VERSION 5.8 ;
BUSBITCHARS "[]" ;
DIVIDERCHAR "/" ;
UNITS
    DATABASE MICRONS 1000 ;
END UNITS

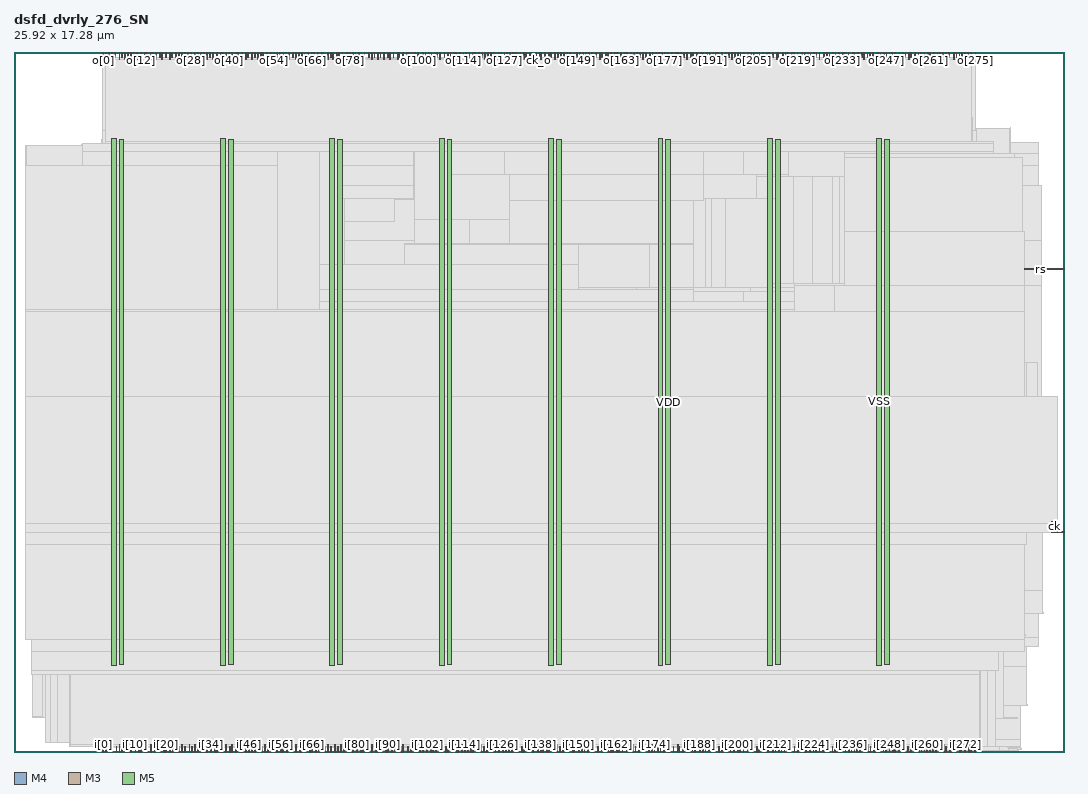
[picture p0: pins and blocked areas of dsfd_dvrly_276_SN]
MACRO dsfd_dvrly_276_SN
  FOREIGN dsfd_dvrly_276_SN 0 0 ;
  CLASS BLOCK ;
  SIZE 25.92 BY 17.28 ;
  PIN ck
    DIRECTION INPUT ;
    USE SIGNAL ;
    PORT
      LAYER M4 ;
        RECT  25.728 5.424 25.92 5.448 ;
    END
    PORT
      LAYER M4 ;
        RECT  25.621 5.424 25.74 5.688 ;
    END
  END ck
  PIN ck_o
    DIRECTION OUTPUT ;
    USE SIGNAL ;
    PORT
      LAYER M3 ;
        RECT  12.96 17.136 12.978 17.28 ;
    END
  END ck_o
  PIN i[0]
    DIRECTION INPUT ;
    USE SIGNAL ;
    PORT
      LAYER M3 ;
        RECT  2.196 0 2.214 0.144 ;
    END
  END i[0]
  PIN i[100]
    DIRECTION INPUT ;
    USE SIGNAL ;
    PORT
      LAYER M3 ;
        RECT  10.008 0 10.026 0.144 ;
    END
  END i[100]
  PIN i[101]
    DIRECTION INPUT ;
    USE SIGNAL ;
    PORT
      LAYER M5 ;
        RECT  10.08 0 10.104 0.192 ;
    END
  END i[101]
  PIN i[102]
    DIRECTION INPUT ;
    USE SIGNAL ;
    PORT
      LAYER M3 ;
        RECT  10.188 0 10.206 0.144 ;
    END
  END i[102]
  PIN i[103]
    DIRECTION INPUT ;
    USE SIGNAL ;
    PORT
      LAYER M5 ;
        RECT  10.272 0 10.296 0.192 ;
    END
  END i[103]
  PIN i[104]
    DIRECTION INPUT ;
    USE SIGNAL ;
    PORT
      LAYER M3 ;
        RECT  10.332 0 10.35 0.144 ;
    END
  END i[104]
  PIN i[105]
    DIRECTION INPUT ;
    USE SIGNAL ;
    PORT
      LAYER M5 ;
        RECT  10.416 0 10.44 0.192 ;
    END
  END i[105]
  PIN i[106]
    DIRECTION INPUT ;
    USE SIGNAL ;
    PORT
      LAYER M3 ;
        RECT  10.476 0 10.494 0.144 ;
    END
  END i[106]
  PIN i[107]
    DIRECTION INPUT ;
    USE SIGNAL ;
    PORT
      LAYER M5 ;
        RECT  10.56 0 10.584 0.192 ;
    END
  END i[107]
  PIN i[108]
    DIRECTION INPUT ;
    USE SIGNAL ;
    PORT
      LAYER M3 ;
        RECT  10.656 0 10.674 0.144 ;
    END
  END i[108]
  PIN i[109]
    DIRECTION INPUT ;
    USE SIGNAL ;
    PORT
      LAYER M5 ;
        RECT  10.704 0 10.728 0.192 ;
    END
  END i[109]
  PIN i[10]
    DIRECTION INPUT ;
    USE SIGNAL ;
    PORT
      LAYER M3 ;
        RECT  2.988 0 3.006 0.144 ;
    END
  END i[10]
  PIN i[110]
    DIRECTION INPUT ;
    USE SIGNAL ;
    PORT
      LAYER M3 ;
        RECT  10.8 0 10.818 0.144 ;
    END
  END i[110]
  PIN i[111]
    DIRECTION INPUT ;
    USE SIGNAL ;
    PORT
      LAYER M5 ;
        RECT  10.896 0 10.92 0.192 ;
    END
  END i[111]
  PIN i[112]
    DIRECTION INPUT ;
    USE SIGNAL ;
    PORT
      LAYER M3 ;
        RECT  10.944 0 10.962 0.144 ;
    END
  END i[112]
  PIN i[113]
    DIRECTION INPUT ;
    USE SIGNAL ;
    PORT
      LAYER M5 ;
        RECT  11.04 0 11.064 0.192 ;
    END
  END i[113]
  PIN i[114]
    DIRECTION INPUT ;
    USE SIGNAL ;
    PORT
      LAYER M3 ;
        RECT  11.124 0 11.142 0.144 ;
    END
  END i[114]
  PIN i[115]
    DIRECTION INPUT ;
    USE SIGNAL ;
    PORT
      LAYER M5 ;
        RECT  11.184 0 11.208 0.192 ;
    END
  END i[115]
  PIN i[116]
    DIRECTION INPUT ;
    USE SIGNAL ;
    PORT
      LAYER M3 ;
        RECT  11.268 0 11.286 0.144 ;
    END
  END i[116]
  PIN i[117]
    DIRECTION INPUT ;
    USE SIGNAL ;
    PORT
      LAYER M5 ;
        RECT  11.328 0 11.352 0.192 ;
    END
  END i[117]
  PIN i[118]
    DIRECTION INPUT ;
    USE SIGNAL ;
    PORT
      LAYER M3 ;
        RECT  11.412 0 11.43 0.144 ;
    END
  END i[118]
  PIN i[119]
    DIRECTION INPUT ;
    USE SIGNAL ;
    PORT
      LAYER M5 ;
        RECT  11.52 0 11.544 0.192 ;
    END
  END i[119]
  PIN i[11]
    DIRECTION INPUT ;
    USE SIGNAL ;
    PORT
      LAYER M5 ;
        RECT  3.072 0 3.096 0.192 ;
    END
  END i[11]
  PIN i[120]
    DIRECTION INPUT ;
    USE SIGNAL ;
    PORT
      LAYER M3 ;
        RECT  11.592 0 11.61 0.144 ;
    END
  END i[120]
  PIN i[121]
    DIRECTION INPUT ;
    USE SIGNAL ;
    PORT
      LAYER M5 ;
        RECT  11.664 0 11.688 0.192 ;
    END
  END i[121]
  PIN i[122]
    DIRECTION INPUT ;
    USE SIGNAL ;
    PORT
      LAYER M3 ;
        RECT  11.736 0 11.754 0.144 ;
    END
  END i[122]
  PIN i[123]
    DIRECTION INPUT ;
    USE SIGNAL ;
    PORT
      LAYER M5 ;
        RECT  11.808 0 11.832 0.192 ;
    END
  END i[123]
  PIN i[124]
    DIRECTION INPUT ;
    USE SIGNAL ;
    PORT
      LAYER M3 ;
        RECT  11.88 0 11.898 0.144 ;
    END
  END i[124]
  PIN i[125]
    DIRECTION INPUT ;
    USE SIGNAL ;
    PORT
      LAYER M5 ;
        RECT  11.952 0 11.976 0.192 ;
    END
  END i[125]
  PIN i[126]
    DIRECTION INPUT ;
    USE SIGNAL ;
    PORT
      LAYER M3 ;
        RECT  12.06 0 12.078 0.144 ;
    END
  END i[126]
  PIN i[127]
    DIRECTION INPUT ;
    USE SIGNAL ;
    PORT
      LAYER M5 ;
        RECT  12.144 0 12.168 0.192 ;
    END
  END i[127]
  PIN i[128]
    DIRECTION INPUT ;
    USE SIGNAL ;
    PORT
      LAYER M3 ;
        RECT  12.204 0 12.222 0.144 ;
    END
  END i[128]
  PIN i[129]
    DIRECTION INPUT ;
    USE SIGNAL ;
    PORT
      LAYER M5 ;
        RECT  12.288 0 12.312 0.192 ;
    END
  END i[129]
  PIN i[12]
    DIRECTION INPUT ;
    USE SIGNAL ;
    PORT
      LAYER M3 ;
        RECT  3.132 0 3.15 0.144 ;
    END
  END i[12]
  PIN i[130]
    DIRECTION INPUT ;
    USE SIGNAL ;
    PORT
      LAYER M3 ;
        RECT  12.348 0 12.366 0.144 ;
    END
  END i[130]
  PIN i[131]
    DIRECTION INPUT ;
    USE SIGNAL ;
    PORT
      LAYER M5 ;
        RECT  12.432 0 12.456 0.192 ;
    END
  END i[131]
  PIN i[132]
    DIRECTION INPUT ;
    USE SIGNAL ;
    PORT
      LAYER M3 ;
        RECT  12.528 0 12.546 0.144 ;
    END
  END i[132]
  PIN i[133]
    DIRECTION INPUT ;
    USE SIGNAL ;
    PORT
      LAYER M5 ;
        RECT  12.576 0 12.6 0.192 ;
    END
  END i[133]
  PIN i[134]
    DIRECTION INPUT ;
    USE SIGNAL ;
    PORT
      LAYER M3 ;
        RECT  12.672 0 12.69 0.144 ;
    END
  END i[134]
  PIN i[135]
    DIRECTION INPUT ;
    USE SIGNAL ;
    PORT
      LAYER M5 ;
        RECT  12.768 0 12.792 0.192 ;
    END
  END i[135]
  PIN i[136]
    DIRECTION INPUT ;
    USE SIGNAL ;
    PORT
      LAYER M3 ;
        RECT  12.816 0 12.834 0.144 ;
    END
  END i[136]
  PIN i[137]
    DIRECTION INPUT ;
    USE SIGNAL ;
    PORT
      LAYER M5 ;
        RECT  12.912 0 12.936 0.192 ;
    END
  END i[137]
  PIN i[138]
    DIRECTION INPUT ;
    USE SIGNAL ;
    PORT
      LAYER M3 ;
        RECT  12.996 0 13.014 0.144 ;
    END
  END i[138]
  PIN i[139]
    DIRECTION INPUT ;
    USE SIGNAL ;
    PORT
      LAYER M5 ;
        RECT  13.056 0 13.08 0.192 ;
    END
  END i[139]
  PIN i[13]
    DIRECTION INPUT ;
    USE SIGNAL ;
    PORT
      LAYER M5 ;
        RECT  3.216 0 3.24 0.192 ;
    END
  END i[13]
  PIN i[140]
    DIRECTION INPUT ;
    USE SIGNAL ;
    PORT
      LAYER M3 ;
        RECT  13.14 0 13.158 0.144 ;
    END
  END i[140]
  PIN i[141]
    DIRECTION INPUT ;
    USE SIGNAL ;
    PORT
      LAYER M5 ;
        RECT  13.2 0 13.224 0.192 ;
    END
  END i[141]
  PIN i[142]
    DIRECTION INPUT ;
    USE SIGNAL ;
    PORT
      LAYER M3 ;
        RECT  13.32 0 13.338 0.144 ;
    END
  END i[142]
  PIN i[143]
    DIRECTION INPUT ;
    USE SIGNAL ;
    PORT
      LAYER M5 ;
        RECT  13.392 0 13.416 0.192 ;
    END
  END i[143]
  PIN i[144]
    DIRECTION INPUT ;
    USE SIGNAL ;
    PORT
      LAYER M3 ;
        RECT  13.464 0 13.482 0.144 ;
    END
  END i[144]
  PIN i[145]
    DIRECTION INPUT ;
    USE SIGNAL ;
    PORT
      LAYER M5 ;
        RECT  13.536 0 13.56 0.192 ;
    END
  END i[145]
  PIN i[146]
    DIRECTION INPUT ;
    USE SIGNAL ;
    PORT
      LAYER M3 ;
        RECT  13.608 0 13.626 0.144 ;
    END
  END i[146]
  PIN i[147]
    DIRECTION INPUT ;
    USE SIGNAL ;
    PORT
      LAYER M5 ;
        RECT  13.68 0 13.704 0.192 ;
    END
  END i[147]
  PIN i[148]
    DIRECTION INPUT ;
    USE SIGNAL ;
    PORT
      LAYER M3 ;
        RECT  13.788 0 13.806 0.144 ;
    END
  END i[148]
  PIN i[149]
    DIRECTION INPUT ;
    USE SIGNAL ;
    PORT
      LAYER M5 ;
        RECT  13.824 0 13.848 0.192 ;
    END
  END i[149]
  PIN i[14]
    DIRECTION INPUT ;
    USE SIGNAL ;
    PORT
      LAYER M3 ;
        RECT  3.276 0 3.294 0.144 ;
    END
  END i[14]
  PIN i[150]
    DIRECTION INPUT ;
    USE SIGNAL ;
    PORT
      LAYER M3 ;
        RECT  13.932 0 13.95 0.144 ;
    END
  END i[150]
  PIN i[151]
    DIRECTION INPUT ;
    USE SIGNAL ;
    PORT
      LAYER M5 ;
        RECT  14.016 0 14.04 0.192 ;
    END
  END i[151]
  PIN i[152]
    DIRECTION INPUT ;
    USE SIGNAL ;
    PORT
      LAYER M3 ;
        RECT  14.076 0 14.094 0.144 ;
    END
  END i[152]
  PIN i[153]
    DIRECTION INPUT ;
    USE SIGNAL ;
    PORT
      LAYER M5 ;
        RECT  14.16 0 14.184 0.192 ;
    END
  END i[153]
  PIN i[154]
    DIRECTION INPUT ;
    USE SIGNAL ;
    PORT
      LAYER M3 ;
        RECT  14.256 0 14.274 0.144 ;
    END
  END i[154]
  PIN i[155]
    DIRECTION INPUT ;
    USE SIGNAL ;
    PORT
      LAYER M5 ;
        RECT  14.304 0 14.328 0.192 ;
    END
  END i[155]
  PIN i[156]
    DIRECTION INPUT ;
    USE SIGNAL ;
    PORT
      LAYER M3 ;
        RECT  14.4 0 14.418 0.144 ;
    END
  END i[156]
  PIN i[157]
    DIRECTION INPUT ;
    USE SIGNAL ;
    PORT
      LAYER M5 ;
        RECT  14.496 0 14.52 0.192 ;
    END
  END i[157]
  PIN i[158]
    DIRECTION INPUT ;
    USE SIGNAL ;
    PORT
      LAYER M3 ;
        RECT  14.544 0 14.562 0.144 ;
    END
  END i[158]
  PIN i[159]
    DIRECTION INPUT ;
    USE SIGNAL ;
    PORT
      LAYER M5 ;
        RECT  14.64 0 14.664 0.192 ;
    END
  END i[159]
  PIN i[15]
    DIRECTION INPUT ;
    USE SIGNAL ;
    PORT
      LAYER M5 ;
        RECT  3.36 0 3.384 0.192 ;
    END
  END i[15]
  PIN i[160]
    DIRECTION INPUT ;
    USE SIGNAL ;
    PORT
      LAYER M3 ;
        RECT  14.724 0 14.742 0.144 ;
    END
  END i[160]
  PIN i[161]
    DIRECTION INPUT ;
    USE SIGNAL ;
    PORT
      LAYER M5 ;
        RECT  14.784 0 14.808 0.192 ;
    END
  END i[161]
  PIN i[162]
    DIRECTION INPUT ;
    USE SIGNAL ;
    PORT
      LAYER M3 ;
        RECT  14.868 0 14.886 0.144 ;
    END
  END i[162]
  PIN i[163]
    DIRECTION INPUT ;
    USE SIGNAL ;
    PORT
      LAYER M5 ;
        RECT  14.928 0 14.952 0.192 ;
    END
  END i[163]
  PIN i[164]
    DIRECTION INPUT ;
    USE SIGNAL ;
    PORT
      LAYER M3 ;
        RECT  15.012 0 15.03 0.144 ;
    END
  END i[164]
  PIN i[165]
    DIRECTION INPUT ;
    USE SIGNAL ;
    PORT
      LAYER M5 ;
        RECT  15.12 0 15.144 0.192 ;
    END
  END i[165]
  PIN i[166]
    DIRECTION INPUT ;
    USE SIGNAL ;
    PORT
      LAYER M3 ;
        RECT  15.192 0 15.21 0.144 ;
    END
  END i[166]
  PIN i[167]
    DIRECTION INPUT ;
    USE SIGNAL ;
    PORT
      LAYER M5 ;
        RECT  15.264 0 15.288 0.192 ;
    END
  END i[167]
  PIN i[168]
    DIRECTION INPUT ;
    USE SIGNAL ;
    PORT
      LAYER M3 ;
        RECT  15.336 0 15.354 0.144 ;
    END
  END i[168]
  PIN i[169]
    DIRECTION INPUT ;
    USE SIGNAL ;
    PORT
      LAYER M5 ;
        RECT  15.408 0 15.432 0.192 ;
    END
  END i[169]
  PIN i[16]
    DIRECTION INPUT ;
    USE SIGNAL ;
    PORT
      LAYER M3 ;
        RECT  3.456 0 3.474 0.144 ;
    END
  END i[16]
  PIN i[170]
    DIRECTION INPUT ;
    USE SIGNAL ;
    PORT
      LAYER M3 ;
        RECT  15.48 0 15.498 0.144 ;
    END
  END i[170]
  PIN i[171]
    DIRECTION INPUT ;
    USE SIGNAL ;
    PORT
      LAYER M5 ;
        RECT  15.552 0 15.576 0.192 ;
    END
  END i[171]
  PIN i[172]
    DIRECTION INPUT ;
    USE SIGNAL ;
    PORT
      LAYER M3 ;
        RECT  15.66 0 15.678 0.144 ;
    END
  END i[172]
  PIN i[173]
    DIRECTION INPUT ;
    USE SIGNAL ;
    PORT
      LAYER M5 ;
        RECT  15.744 0 15.768 0.192 ;
    END
  END i[173]
  PIN i[174]
    DIRECTION INPUT ;
    USE SIGNAL ;
    PORT
      LAYER M3 ;
        RECT  15.804 0 15.822 0.144 ;
    END
  END i[174]
  PIN i[175]
    DIRECTION INPUT ;
    USE SIGNAL ;
    PORT
      LAYER M5 ;
        RECT  15.888 0 15.912 0.192 ;
    END
  END i[175]
  PIN i[176]
    DIRECTION INPUT ;
    USE SIGNAL ;
    PORT
      LAYER M3 ;
        RECT  15.948 0 15.966 0.144 ;
    END
  END i[176]
  PIN i[177]
    DIRECTION INPUT ;
    USE SIGNAL ;
    PORT
      LAYER M5 ;
        RECT  16.032 0 16.056 0.192 ;
    END
  END i[177]
  PIN i[178]
    DIRECTION INPUT ;
    USE SIGNAL ;
    PORT
      LAYER M3 ;
        RECT  16.128 0 16.146 0.144 ;
    END
  END i[178]
  PIN i[179]
    DIRECTION INPUT ;
    USE SIGNAL ;
    PORT
      LAYER M5 ;
        RECT  16.176 0 16.2 0.192 ;
    END
  END i[179]
  PIN i[17]
    DIRECTION INPUT ;
    USE SIGNAL ;
    PORT
      LAYER M5 ;
        RECT  3.504 0 3.528 0.192 ;
    END
  END i[17]
  PIN i[180]
    DIRECTION INPUT ;
    USE SIGNAL ;
    PORT
      LAYER M3 ;
        RECT  16.272 0 16.29 0.144 ;
    END
  END i[180]
  PIN i[181]
    DIRECTION INPUT ;
    USE SIGNAL ;
    PORT
      LAYER M5 ;
        RECT  16.368 0 16.392 0.192 ;
    END
  END i[181]
  PIN i[182]
    DIRECTION INPUT ;
    USE SIGNAL ;
    PORT
      LAYER M3 ;
        RECT  16.416 0 16.434 0.144 ;
    END
  END i[182]
  PIN i[183]
    DIRECTION INPUT ;
    USE SIGNAL ;
    PORT
      LAYER M5 ;
        RECT  16.512 0 16.536 0.192 ;
    END
  END i[183]
  PIN i[184]
    DIRECTION INPUT ;
    USE SIGNAL ;
    PORT
      LAYER M3 ;
        RECT  16.596 0 16.614 0.144 ;
    END
  END i[184]
  PIN i[185]
    DIRECTION INPUT ;
    USE SIGNAL ;
    PORT
      LAYER M5 ;
        RECT  16.656 0 16.68 0.192 ;
    END
  END i[185]
  PIN i[186]
    DIRECTION INPUT ;
    USE SIGNAL ;
    PORT
      LAYER M3 ;
        RECT  16.74 0 16.758 0.144 ;
    END
  END i[186]
  PIN i[187]
    DIRECTION INPUT ;
    USE SIGNAL ;
    PORT
      LAYER M5 ;
        RECT  16.8 0 16.824 0.192 ;
    END
  END i[187]
  PIN i[188]
    DIRECTION INPUT ;
    USE SIGNAL ;
    PORT
      LAYER M3 ;
        RECT  16.92 0 16.938 0.144 ;
    END
  END i[188]
  PIN i[189]
    DIRECTION INPUT ;
    USE SIGNAL ;
    PORT
      LAYER M5 ;
        RECT  16.992 0 17.016 0.192 ;
    END
  END i[189]
  PIN i[18]
    DIRECTION INPUT ;
    USE SIGNAL ;
    PORT
      LAYER M3 ;
        RECT  3.6 0 3.618 0.144 ;
    END
  END i[18]
  PIN i[190]
    DIRECTION INPUT ;
    USE SIGNAL ;
    PORT
      LAYER M3 ;
        RECT  17.064 0 17.082 0.144 ;
    END
  END i[190]
  PIN i[191]
    DIRECTION INPUT ;
    USE SIGNAL ;
    PORT
      LAYER M5 ;
        RECT  17.136 0 17.16 0.192 ;
    END
  END i[191]
  PIN i[192]
    DIRECTION INPUT ;
    USE SIGNAL ;
    PORT
      LAYER M3 ;
        RECT  17.208 0 17.226 0.144 ;
    END
  END i[192]
  PIN i[193]
    DIRECTION INPUT ;
    USE SIGNAL ;
    PORT
      LAYER M5 ;
        RECT  17.28 0 17.304 0.192 ;
    END
  END i[193]
  PIN i[194]
    DIRECTION INPUT ;
    USE SIGNAL ;
    PORT
      LAYER M3 ;
        RECT  17.388 0 17.406 0.144 ;
    END
  END i[194]
  PIN i[195]
    DIRECTION INPUT ;
    USE SIGNAL ;
    PORT
      LAYER M5 ;
        RECT  17.472 0 17.496 0.192 ;
    END
  END i[195]
  PIN i[196]
    DIRECTION INPUT ;
    USE SIGNAL ;
    PORT
      LAYER M3 ;
        RECT  17.532 0 17.55 0.144 ;
    END
  END i[196]
  PIN i[197]
    DIRECTION INPUT ;
    USE SIGNAL ;
    PORT
      LAYER M5 ;
        RECT  17.616 0 17.64 0.192 ;
    END
  END i[197]
  PIN i[198]
    DIRECTION INPUT ;
    USE SIGNAL ;
    PORT
      LAYER M3 ;
        RECT  17.676 0 17.694 0.144 ;
    END
  END i[198]
  PIN i[199]
    DIRECTION INPUT ;
    USE SIGNAL ;
    PORT
      LAYER M5 ;
        RECT  17.76 0 17.784 0.192 ;
    END
  END i[199]
  PIN i[19]
    DIRECTION INPUT ;
    USE SIGNAL ;
    PORT
      LAYER M5 ;
        RECT  3.696 0 3.72 0.192 ;
    END
  END i[19]
  PIN i[1]
    DIRECTION INPUT ;
    USE SIGNAL ;
    PORT
      LAYER M5 ;
        RECT  2.256 0 2.28 0.192 ;
    END
  END i[1]
  PIN i[200]
    DIRECTION INPUT ;
    USE SIGNAL ;
    PORT
      LAYER M3 ;
        RECT  17.856 0 17.874 0.144 ;
    END
  END i[200]
  PIN i[201]
    DIRECTION INPUT ;
    USE SIGNAL ;
    PORT
      LAYER M5 ;
        RECT  17.904 0 17.928 0.192 ;
    END
  END i[201]
  PIN i[202]
    DIRECTION INPUT ;
    USE SIGNAL ;
    PORT
      LAYER M3 ;
        RECT  18 0 18.018 0.144 ;
    END
  END i[202]
  PIN i[203]
    DIRECTION INPUT ;
    USE SIGNAL ;
    PORT
      LAYER M5 ;
        RECT  18.096 0 18.12 0.192 ;
    END
  END i[203]
  PIN i[204]
    DIRECTION INPUT ;
    USE SIGNAL ;
    PORT
      LAYER M3 ;
        RECT  18.144 0 18.162 0.144 ;
    END
  END i[204]
  PIN i[205]
    DIRECTION INPUT ;
    USE SIGNAL ;
    PORT
      LAYER M5 ;
        RECT  18.24 0 18.264 0.192 ;
    END
  END i[205]
  PIN i[206]
    DIRECTION INPUT ;
    USE SIGNAL ;
    PORT
      LAYER M3 ;
        RECT  18.324 0 18.342 0.144 ;
    END
  END i[206]
  PIN i[207]
    DIRECTION INPUT ;
    USE SIGNAL ;
    PORT
      LAYER M5 ;
        RECT  18.384 0 18.408 0.192 ;
    END
  END i[207]
  PIN i[208]
    DIRECTION INPUT ;
    USE SIGNAL ;
    PORT
      LAYER M3 ;
        RECT  18.468 0 18.486 0.144 ;
    END
  END i[208]
  PIN i[209]
    DIRECTION INPUT ;
    USE SIGNAL ;
    PORT
      LAYER M5 ;
        RECT  18.528 0 18.552 0.192 ;
    END
  END i[209]
  PIN i[20]
    DIRECTION INPUT ;
    USE SIGNAL ;
    PORT
      LAYER M3 ;
        RECT  3.744 0 3.762 0.144 ;
    END
  END i[20]
  PIN i[210]
    DIRECTION INPUT ;
    USE SIGNAL ;
    PORT
      LAYER M3 ;
        RECT  18.612 0 18.63 0.144 ;
    END
  END i[210]
  PIN i[211]
    DIRECTION INPUT ;
    USE SIGNAL ;
    PORT
      LAYER M5 ;
        RECT  18.72 0 18.744 0.192 ;
    END
  END i[211]
  PIN i[212]
    DIRECTION INPUT ;
    USE SIGNAL ;
    PORT
      LAYER M3 ;
        RECT  18.792 0 18.81 0.144 ;
    END
  END i[212]
  PIN i[213]
    DIRECTION INPUT ;
    USE SIGNAL ;
    PORT
      LAYER M5 ;
        RECT  18.864 0 18.888 0.192 ;
    END
  END i[213]
  PIN i[214]
    DIRECTION INPUT ;
    USE SIGNAL ;
    PORT
      LAYER M3 ;
        RECT  18.936 0 18.954 0.144 ;
    END
  END i[214]
  PIN i[215]
    DIRECTION INPUT ;
    USE SIGNAL ;
    PORT
      LAYER M5 ;
        RECT  19.008 0 19.032 0.192 ;
    END
  END i[215]
  PIN i[216]
    DIRECTION INPUT ;
    USE SIGNAL ;
    PORT
      LAYER M3 ;
        RECT  19.08 0 19.098 0.144 ;
    END
  END i[216]
  PIN i[217]
    DIRECTION INPUT ;
    USE SIGNAL ;
    PORT
      LAYER M5 ;
        RECT  19.152 0 19.176 0.192 ;
    END
  END i[217]
  PIN i[218]
    DIRECTION INPUT ;
    USE SIGNAL ;
    PORT
      LAYER M3 ;
        RECT  19.26 0 19.278 0.144 ;
    END
  END i[218]
  PIN i[219]
    DIRECTION INPUT ;
    USE SIGNAL ;
    PORT
      LAYER M5 ;
        RECT  19.344 0 19.368 0.192 ;
    END
  END i[219]
  PIN i[21]
    DIRECTION INPUT ;
    USE SIGNAL ;
    PORT
      LAYER M5 ;
        RECT  3.84 0 3.864 0.192 ;
    END
  END i[21]
  PIN i[220]
    DIRECTION INPUT ;
    USE SIGNAL ;
    PORT
      LAYER M3 ;
        RECT  19.404 0 19.422 0.144 ;
    END
  END i[220]
  PIN i[221]
    DIRECTION INPUT ;
    USE SIGNAL ;
    PORT
      LAYER M5 ;
        RECT  19.488 0 19.512 0.192 ;
    END
  END i[221]
  PIN i[222]
    DIRECTION INPUT ;
    USE SIGNAL ;
    PORT
      LAYER M3 ;
        RECT  19.548 0 19.566 0.144 ;
    END
  END i[222]
  PIN i[223]
    DIRECTION INPUT ;
    USE SIGNAL ;
    PORT
      LAYER M5 ;
        RECT  19.632 0 19.656 0.192 ;
    END
  END i[223]
  PIN i[224]
    DIRECTION INPUT ;
    USE SIGNAL ;
    PORT
      LAYER M3 ;
        RECT  19.728 0 19.746 0.144 ;
    END
  END i[224]
  PIN i[225]
    DIRECTION INPUT ;
    USE SIGNAL ;
    PORT
      LAYER M5 ;
        RECT  19.776 0 19.8 0.192 ;
    END
  END i[225]
  PIN i[226]
    DIRECTION INPUT ;
    USE SIGNAL ;
    PORT
      LAYER M3 ;
        RECT  19.872 0 19.89 0.144 ;
    END
  END i[226]
  PIN i[227]
    DIRECTION INPUT ;
    USE SIGNAL ;
    PORT
      LAYER M5 ;
        RECT  19.968 0 19.992 0.192 ;
    END
  END i[227]
  PIN i[228]
    DIRECTION INPUT ;
    USE SIGNAL ;
    PORT
      LAYER M3 ;
        RECT  20.016 0 20.034 0.144 ;
    END
  END i[228]
  PIN i[229]
    DIRECTION INPUT ;
    USE SIGNAL ;
    PORT
      LAYER M5 ;
        RECT  20.112 0 20.136 0.192 ;
    END
  END i[229]
  PIN i[22]
    DIRECTION INPUT ;
    USE SIGNAL ;
    PORT
      LAYER M3 ;
        RECT  3.924 0 3.942 0.144 ;
    END
  END i[22]
  PIN i[230]
    DIRECTION INPUT ;
    USE SIGNAL ;
    PORT
      LAYER M3 ;
        RECT  20.196 0 20.214 0.144 ;
    END
  END i[230]
  PIN i[231]
    DIRECTION INPUT ;
    USE SIGNAL ;
    PORT
      LAYER M5 ;
        RECT  20.256 0 20.28 0.192 ;
    END
  END i[231]
  PIN i[232]
    DIRECTION INPUT ;
    USE SIGNAL ;
    PORT
      LAYER M3 ;
        RECT  20.34 0 20.358 0.144 ;
    END
  END i[232]
  PIN i[233]
    DIRECTION INPUT ;
    USE SIGNAL ;
    PORT
      LAYER M5 ;
        RECT  20.4 0 20.424 0.192 ;
    END
  END i[233]
  PIN i[234]
    DIRECTION INPUT ;
    USE SIGNAL ;
    PORT
      LAYER M3 ;
        RECT  20.52 0 20.538 0.144 ;
    END
  END i[234]
  PIN i[235]
    DIRECTION INPUT ;
    USE SIGNAL ;
    PORT
      LAYER M5 ;
        RECT  20.592 0 20.616 0.192 ;
    END
  END i[235]
  PIN i[236]
    DIRECTION INPUT ;
    USE SIGNAL ;
    PORT
      LAYER M3 ;
        RECT  20.664 0 20.682 0.144 ;
    END
  END i[236]
  PIN i[237]
    DIRECTION INPUT ;
    USE SIGNAL ;
    PORT
      LAYER M5 ;
        RECT  20.736 0 20.76 0.192 ;
    END
  END i[237]
  PIN i[238]
    DIRECTION INPUT ;
    USE SIGNAL ;
    PORT
      LAYER M3 ;
        RECT  20.808 0 20.826 0.144 ;
    END
  END i[238]
  PIN i[239]
    DIRECTION INPUT ;
    USE SIGNAL ;
    PORT
      LAYER M5 ;
        RECT  20.88 0 20.904 0.192 ;
    END
  END i[239]
  PIN i[23]
    DIRECTION INPUT ;
    USE SIGNAL ;
    PORT
      LAYER M5 ;
        RECT  3.984 0 4.008 0.192 ;
    END
  END i[23]
  PIN i[240]
    DIRECTION INPUT ;
    USE SIGNAL ;
    PORT
      LAYER M3 ;
        RECT  20.988 0 21.006 0.144 ;
    END
  END i[240]
  PIN i[241]
    DIRECTION INPUT ;
    USE SIGNAL ;
    PORT
      LAYER M5 ;
        RECT  21.072 0 21.096 0.192 ;
    END
  END i[241]
  PIN i[242]
    DIRECTION INPUT ;
    USE SIGNAL ;
    PORT
      LAYER M3 ;
        RECT  21.132 0 21.15 0.144 ;
    END
  END i[242]
  PIN i[243]
    DIRECTION INPUT ;
    USE SIGNAL ;
    PORT
      LAYER M5 ;
        RECT  21.216 0 21.24 0.192 ;
    END
  END i[243]
  PIN i[244]
    DIRECTION INPUT ;
    USE SIGNAL ;
    PORT
      LAYER M3 ;
        RECT  21.276 0 21.294 0.144 ;
    END
  END i[244]
  PIN i[245]
    DIRECTION INPUT ;
    USE SIGNAL ;
    PORT
      LAYER M5 ;
        RECT  21.36 0 21.384 0.192 ;
    END
  END i[245]
  PIN i[246]
    DIRECTION INPUT ;
    USE SIGNAL ;
    PORT
      LAYER M3 ;
        RECT  21.456 0 21.474 0.144 ;
    END
  END i[246]
  PIN i[247]
    DIRECTION INPUT ;
    USE SIGNAL ;
    PORT
      LAYER M5 ;
        RECT  21.504 0 21.528 0.192 ;
    END
  END i[247]
  PIN i[248]
    DIRECTION INPUT ;
    USE SIGNAL ;
    PORT
      LAYER M3 ;
        RECT  21.6 0 21.618 0.144 ;
    END
  END i[248]
  PIN i[249]
    DIRECTION INPUT ;
    USE SIGNAL ;
    PORT
      LAYER M5 ;
        RECT  21.696 0 21.72 0.192 ;
    END
  END i[249]
  PIN i[24]
    DIRECTION INPUT ;
    USE SIGNAL ;
    PORT
      LAYER M3 ;
        RECT  4.068 0 4.086 0.144 ;
    END
  END i[24]
  PIN i[250]
    DIRECTION INPUT ;
    USE SIGNAL ;
    PORT
      LAYER M3 ;
        RECT  21.744 0 21.762 0.144 ;
    END
  END i[250]
  PIN i[251]
    DIRECTION INPUT ;
    USE SIGNAL ;
    PORT
      LAYER M5 ;
        RECT  21.84 0 21.864 0.192 ;
    END
  END i[251]
  PIN i[252]
    DIRECTION INPUT ;
    USE SIGNAL ;
    PORT
      LAYER M3 ;
        RECT  21.924 0 21.942 0.144 ;
    END
  END i[252]
  PIN i[253]
    DIRECTION INPUT ;
    USE SIGNAL ;
    PORT
      LAYER M5 ;
        RECT  21.984 0 22.008 0.192 ;
    END
  END i[253]
  PIN i[254]
    DIRECTION INPUT ;
    USE SIGNAL ;
    PORT
      LAYER M3 ;
        RECT  22.068 0 22.086 0.144 ;
    END
  END i[254]
  PIN i[255]
    DIRECTION INPUT ;
    USE SIGNAL ;
    PORT
      LAYER M5 ;
        RECT  22.128 0 22.152 0.192 ;
    END
  END i[255]
  PIN i[256]
    DIRECTION INPUT ;
    USE SIGNAL ;
    PORT
      LAYER M3 ;
        RECT  22.212 0 22.23 0.144 ;
    END
  END i[256]
  PIN i[257]
    DIRECTION INPUT ;
    USE SIGNAL ;
    PORT
      LAYER M5 ;
        RECT  22.32 0 22.344 0.192 ;
    END
  END i[257]
  PIN i[258]
    DIRECTION INPUT ;
    USE SIGNAL ;
    PORT
      LAYER M3 ;
        RECT  22.392 0 22.41 0.144 ;
    END
  END i[258]
  PIN i[259]
    DIRECTION INPUT ;
    USE SIGNAL ;
    PORT
      LAYER M5 ;
        RECT  22.464 0 22.488 0.192 ;
    END
  END i[259]
  PIN i[25]
    DIRECTION INPUT ;
    USE SIGNAL ;
    PORT
      LAYER M5 ;
        RECT  4.128 0 4.152 0.192 ;
    END
  END i[25]
  PIN i[260]
    DIRECTION INPUT ;
    USE SIGNAL ;
    PORT
      LAYER M3 ;
        RECT  22.536 0 22.554 0.144 ;
    END
  END i[260]
  PIN i[261]
    DIRECTION INPUT ;
    USE SIGNAL ;
    PORT
      LAYER M5 ;
        RECT  22.608 0 22.632 0.192 ;
    END
  END i[261]
  PIN i[262]
    DIRECTION INPUT ;
    USE SIGNAL ;
    PORT
      LAYER M3 ;
        RECT  22.68 0 22.698 0.144 ;
    END
  END i[262]
  PIN i[263]
    DIRECTION INPUT ;
    USE SIGNAL ;
    PORT
      LAYER M5 ;
        RECT  22.752 0 22.776 0.192 ;
    END
  END i[263]
  PIN i[264]
    DIRECTION INPUT ;
    USE SIGNAL ;
    PORT
      LAYER M3 ;
        RECT  22.86 0 22.878 0.144 ;
    END
  END i[264]
  PIN i[265]
    DIRECTION INPUT ;
    USE SIGNAL ;
    PORT
      LAYER M5 ;
        RECT  22.944 0 22.968 0.192 ;
    END
  END i[265]
  PIN i[266]
    DIRECTION INPUT ;
    USE SIGNAL ;
    PORT
      LAYER M3 ;
        RECT  23.004 0 23.022 0.144 ;
    END
  END i[266]
  PIN i[267]
    DIRECTION INPUT ;
    USE SIGNAL ;
    PORT
      LAYER M5 ;
        RECT  23.088 0 23.112 0.192 ;
    END
  END i[267]
  PIN i[268]
    DIRECTION INPUT ;
    USE SIGNAL ;
    PORT
      LAYER M3 ;
        RECT  23.148 0 23.166 0.144 ;
    END
  END i[268]
  PIN i[269]
    DIRECTION INPUT ;
    USE SIGNAL ;
    PORT
      LAYER M5 ;
        RECT  23.232 0 23.256 0.192 ;
    END
  END i[269]
  PIN i[26]
    DIRECTION INPUT ;
    USE SIGNAL ;
    PORT
      LAYER M3 ;
        RECT  4.212 0 4.23 0.144 ;
    END
  END i[26]
  PIN i[270]
    DIRECTION INPUT ;
    USE SIGNAL ;
    PORT
      LAYER M3 ;
        RECT  23.328 0 23.346 0.144 ;
    END
  END i[270]
  PIN i[271]
    DIRECTION INPUT ;
    USE SIGNAL ;
    PORT
      LAYER M5 ;
        RECT  23.376 0 23.4 0.192 ;
    END
  END i[271]
  PIN i[272]
    DIRECTION INPUT ;
    USE SIGNAL ;
    PORT
      LAYER M3 ;
        RECT  23.472 0 23.49 0.144 ;
    END
  END i[272]
  PIN i[273]
    DIRECTION INPUT ;
    USE SIGNAL ;
    PORT
      LAYER M5 ;
        RECT  23.568 0 23.592 0.192 ;
    END
  END i[273]
  PIN i[274]
    DIRECTION INPUT ;
    USE SIGNAL ;
    PORT
      LAYER M3 ;
        RECT  23.616 0 23.634 0.144 ;
    END
  END i[274]
  PIN i[275]
    DIRECTION INPUT ;
    USE SIGNAL ;
    PORT
      LAYER M5 ;
        RECT  23.712 0 23.736 0.192 ;
    END
  END i[275]
  PIN i[27]
    DIRECTION INPUT ;
    USE SIGNAL ;
    PORT
      LAYER M5 ;
        RECT  4.32 0 4.344 0.192 ;
    END
  END i[27]
  PIN i[28]
    DIRECTION INPUT ;
    USE SIGNAL ;
    PORT
      LAYER M3 ;
        RECT  4.392 0 4.41 0.144 ;
    END
  END i[28]
  PIN i[29]
    DIRECTION INPUT ;
    USE SIGNAL ;
    PORT
      LAYER M5 ;
        RECT  4.464 0 4.488 0.192 ;
    END
  END i[29]
  PIN i[2]
    DIRECTION INPUT ;
    USE SIGNAL ;
    PORT
      LAYER M3 ;
        RECT  2.34 0 2.358 0.144 ;
    END
  END i[2]
  PIN i[30]
    DIRECTION INPUT ;
    USE SIGNAL ;
    PORT
      LAYER M3 ;
        RECT  4.536 0 4.554 0.144 ;
    END
  END i[30]
  PIN i[31]
    DIRECTION INPUT ;
    USE SIGNAL ;
    PORT
      LAYER M5 ;
        RECT  4.608 0 4.632 0.192 ;
    END
  END i[31]
  PIN i[32]
    DIRECTION INPUT ;
    USE SIGNAL ;
    PORT
      LAYER M3 ;
        RECT  4.68 0 4.698 0.144 ;
    END
  END i[32]
  PIN i[33]
    DIRECTION INPUT ;
    USE SIGNAL ;
    PORT
      LAYER M5 ;
        RECT  4.752 0 4.776 0.192 ;
    END
  END i[33]
  PIN i[34]
    DIRECTION INPUT ;
    USE SIGNAL ;
    PORT
      LAYER M3 ;
        RECT  4.86 0 4.878 0.144 ;
    END
  END i[34]
  PIN i[35]
    DIRECTION INPUT ;
    USE SIGNAL ;
    PORT
      LAYER M5 ;
        RECT  4.944 0 4.968 0.192 ;
    END
  END i[35]
  PIN i[36]
    DIRECTION INPUT ;
    USE SIGNAL ;
    PORT
      LAYER M3 ;
        RECT  5.004 0 5.022 0.144 ;
    END
  END i[36]
  PIN i[37]
    DIRECTION INPUT ;
    USE SIGNAL ;
    PORT
      LAYER M5 ;
        RECT  5.088 0 5.112 0.192 ;
    END
  END i[37]
  PIN i[38]
    DIRECTION INPUT ;
    USE SIGNAL ;
    PORT
      LAYER M3 ;
        RECT  5.148 0 5.166 0.144 ;
    END
  END i[38]
  PIN i[39]
    DIRECTION INPUT ;
    USE SIGNAL ;
    PORT
      LAYER M5 ;
        RECT  5.232 0 5.256 0.192 ;
    END
  END i[39]
  PIN i[3]
    DIRECTION INPUT ;
    USE SIGNAL ;
    PORT
      LAYER M5 ;
        RECT  2.4 0 2.424 0.192 ;
    END
  END i[3]
  PIN i[40]
    DIRECTION INPUT ;
    USE SIGNAL ;
    PORT
      LAYER M3 ;
        RECT  5.328 0 5.346 0.144 ;
    END
  END i[40]
  PIN i[41]
    DIRECTION INPUT ;
    USE SIGNAL ;
    PORT
      LAYER M5 ;
        RECT  5.376 0 5.4 0.192 ;
    END
  END i[41]
  PIN i[42]
    DIRECTION INPUT ;
    USE SIGNAL ;
    PORT
      LAYER M3 ;
        RECT  5.472 0 5.49 0.144 ;
    END
  END i[42]
  PIN i[43]
    DIRECTION INPUT ;
    USE SIGNAL ;
    PORT
      LAYER M5 ;
        RECT  5.568 0 5.592 0.192 ;
    END
  END i[43]
  PIN i[44]
    DIRECTION INPUT ;
    USE SIGNAL ;
    PORT
      LAYER M3 ;
        RECT  5.616 0 5.634 0.144 ;
    END
  END i[44]
  PIN i[45]
    DIRECTION INPUT ;
    USE SIGNAL ;
    PORT
      LAYER M5 ;
        RECT  5.712 0 5.736 0.192 ;
    END
  END i[45]
  PIN i[46]
    DIRECTION INPUT ;
    USE SIGNAL ;
    PORT
      LAYER M3 ;
        RECT  5.796 0 5.814 0.144 ;
    END
  END i[46]
  PIN i[47]
    DIRECTION INPUT ;
    USE SIGNAL ;
    PORT
      LAYER M5 ;
        RECT  5.856 0 5.88 0.192 ;
    END
  END i[47]
  PIN i[48]
    DIRECTION INPUT ;
    USE SIGNAL ;
    PORT
      LAYER M3 ;
        RECT  5.94 0 5.958 0.144 ;
    END
  END i[48]
  PIN i[49]
    DIRECTION INPUT ;
    USE SIGNAL ;
    PORT
      LAYER M5 ;
        RECT  6 0 6.024 0.192 ;
    END
  END i[49]
  PIN i[4]
    DIRECTION INPUT ;
    USE SIGNAL ;
    PORT
      LAYER M3 ;
        RECT  2.52 0 2.538 0.144 ;
    END
  END i[4]
  PIN i[50]
    DIRECTION INPUT ;
    USE SIGNAL ;
    PORT
      LAYER M3 ;
        RECT  6.12 0 6.138 0.144 ;
    END
  END i[50]
  PIN i[51]
    DIRECTION INPUT ;
    USE SIGNAL ;
    PORT
      LAYER M5 ;
        RECT  6.192 0 6.216 0.192 ;
    END
  END i[51]
  PIN i[52]
    DIRECTION INPUT ;
    USE SIGNAL ;
    PORT
      LAYER M3 ;
        RECT  6.264 0 6.282 0.144 ;
    END
  END i[52]
  PIN i[53]
    DIRECTION INPUT ;
    USE SIGNAL ;
    PORT
      LAYER M5 ;
        RECT  6.336 0 6.36 0.192 ;
    END
  END i[53]
  PIN i[54]
    DIRECTION INPUT ;
    USE SIGNAL ;
    PORT
      LAYER M3 ;
        RECT  6.408 0 6.426 0.144 ;
    END
  END i[54]
  PIN i[55]
    DIRECTION INPUT ;
    USE SIGNAL ;
    PORT
      LAYER M5 ;
        RECT  6.48 0 6.504 0.192 ;
    END
  END i[55]
  PIN i[56]
    DIRECTION INPUT ;
    USE SIGNAL ;
    PORT
      LAYER M3 ;
        RECT  6.588 0 6.606 0.144 ;
    END
  END i[56]
  PIN i[57]
    DIRECTION INPUT ;
    USE SIGNAL ;
    PORT
      LAYER M5 ;
        RECT  6.624 0 6.648 0.192 ;
    END
  END i[57]
  PIN i[58]
    DIRECTION INPUT ;
    USE SIGNAL ;
    PORT
      LAYER M3 ;
        RECT  6.732 0 6.75 0.144 ;
    END
  END i[58]
  PIN i[59]
    DIRECTION INPUT ;
    USE SIGNAL ;
    PORT
      LAYER M5 ;
        RECT  6.816 0 6.84 0.192 ;
    END
  END i[59]
  PIN i[5]
    DIRECTION INPUT ;
    USE SIGNAL ;
    PORT
      LAYER M5 ;
        RECT  2.592 0 2.616 0.192 ;
    END
  END i[5]
  PIN i[60]
    DIRECTION INPUT ;
    USE SIGNAL ;
    PORT
      LAYER M3 ;
        RECT  6.876 0 6.894 0.144 ;
    END
  END i[60]
  PIN i[61]
    DIRECTION INPUT ;
    USE SIGNAL ;
    PORT
      LAYER M5 ;
        RECT  6.96 0 6.984 0.192 ;
    END
  END i[61]
  PIN i[62]
    DIRECTION INPUT ;
    USE SIGNAL ;
    PORT
      LAYER M3 ;
        RECT  7.056 0 7.074 0.144 ;
    END
  END i[62]
  PIN i[63]
    DIRECTION INPUT ;
    USE SIGNAL ;
    PORT
      LAYER M5 ;
        RECT  7.104 0 7.128 0.192 ;
    END
  END i[63]
  PIN i[64]
    DIRECTION INPUT ;
    USE SIGNAL ;
    PORT
      LAYER M3 ;
        RECT  7.2 0 7.218 0.144 ;
    END
  END i[64]
  PIN i[65]
    DIRECTION INPUT ;
    USE SIGNAL ;
    PORT
      LAYER M5 ;
        RECT  7.296 0 7.32 0.192 ;
    END
  END i[65]
  PIN i[66]
    DIRECTION INPUT ;
    USE SIGNAL ;
    PORT
      LAYER M3 ;
        RECT  7.344 0 7.362 0.144 ;
    END
  END i[66]
  PIN i[67]
    DIRECTION INPUT ;
    USE SIGNAL ;
    PORT
      LAYER M5 ;
        RECT  7.44 0 7.464 0.192 ;
    END
  END i[67]
  PIN i[68]
    DIRECTION INPUT ;
    USE SIGNAL ;
    PORT
      LAYER M3 ;
        RECT  7.524 0 7.542 0.144 ;
    END
  END i[68]
  PIN i[69]
    DIRECTION INPUT ;
    USE SIGNAL ;
    PORT
      LAYER M5 ;
        RECT  7.584 0 7.608 0.192 ;
    END
  END i[69]
  PIN i[6]
    DIRECTION INPUT ;
    USE SIGNAL ;
    PORT
      LAYER M3 ;
        RECT  2.664 0 2.682 0.144 ;
    END
  END i[6]
  PIN i[70]
    DIRECTION INPUT ;
    USE SIGNAL ;
    PORT
      LAYER M3 ;
        RECT  7.668 0 7.686 0.144 ;
    END
  END i[70]
  PIN i[71]
    DIRECTION INPUT ;
    USE SIGNAL ;
    PORT
      LAYER M5 ;
        RECT  7.728 0 7.752 0.192 ;
    END
  END i[71]
  PIN i[72]
    DIRECTION INPUT ;
    USE SIGNAL ;
    PORT
      LAYER M3 ;
        RECT  7.812 0 7.83 0.144 ;
    END
  END i[72]
  PIN i[73]
    DIRECTION INPUT ;
    USE SIGNAL ;
    PORT
      LAYER M5 ;
        RECT  7.92 0 7.944 0.192 ;
    END
  END i[73]
  PIN i[74]
    DIRECTION INPUT ;
    USE SIGNAL ;
    PORT
      LAYER M3 ;
        RECT  7.992 0 8.01 0.144 ;
    END
  END i[74]
  PIN i[75]
    DIRECTION INPUT ;
    USE SIGNAL ;
    PORT
      LAYER M5 ;
        RECT  8.064 0 8.088 0.192 ;
    END
  END i[75]
  PIN i[76]
    DIRECTION INPUT ;
    USE SIGNAL ;
    PORT
      LAYER M3 ;
        RECT  8.136 0 8.154 0.144 ;
    END
  END i[76]
  PIN i[77]
    DIRECTION INPUT ;
    USE SIGNAL ;
    PORT
      LAYER M5 ;
        RECT  8.208 0 8.232 0.192 ;
    END
  END i[77]
  PIN i[78]
    DIRECTION INPUT ;
    USE SIGNAL ;
    PORT
      LAYER M3 ;
        RECT  8.28 0 8.298 0.144 ;
    END
  END i[78]
  PIN i[79]
    DIRECTION INPUT ;
    USE SIGNAL ;
    PORT
      LAYER M5 ;
        RECT  8.352 0 8.376 0.192 ;
    END
  END i[79]
  PIN i[7]
    DIRECTION INPUT ;
    USE SIGNAL ;
    PORT
      LAYER M5 ;
        RECT  2.736 0 2.76 0.192 ;
    END
  END i[7]
  PIN i[80]
    DIRECTION INPUT ;
    USE SIGNAL ;
    PORT
      LAYER M3 ;
        RECT  8.46 0 8.478 0.144 ;
    END
  END i[80]
  PIN i[81]
    DIRECTION INPUT ;
    USE SIGNAL ;
    PORT
      LAYER M5 ;
        RECT  8.544 0 8.568 0.192 ;
    END
  END i[81]
  PIN i[82]
    DIRECTION INPUT ;
    USE SIGNAL ;
    PORT
      LAYER M3 ;
        RECT  8.604 0 8.622 0.144 ;
    END
  END i[82]
  PIN i[83]
    DIRECTION INPUT ;
    USE SIGNAL ;
    PORT
      LAYER M5 ;
        RECT  8.688 0 8.712 0.192 ;
    END
  END i[83]
  PIN i[84]
    DIRECTION INPUT ;
    USE SIGNAL ;
    PORT
      LAYER M3 ;
        RECT  8.748 0 8.766 0.144 ;
    END
  END i[84]
  PIN i[85]
    DIRECTION INPUT ;
    USE SIGNAL ;
    PORT
      LAYER M5 ;
        RECT  8.832 0 8.856 0.192 ;
    END
  END i[85]
  PIN i[86]
    DIRECTION INPUT ;
    USE SIGNAL ;
    PORT
      LAYER M3 ;
        RECT  8.928 0 8.946 0.144 ;
    END
  END i[86]
  PIN i[87]
    DIRECTION INPUT ;
    USE SIGNAL ;
    PORT
      LAYER M5 ;
        RECT  8.976 0 9 0.192 ;
    END
  END i[87]
  PIN i[88]
    DIRECTION INPUT ;
    USE SIGNAL ;
    PORT
      LAYER M3 ;
        RECT  9.072 0 9.09 0.144 ;
    END
  END i[88]
  PIN i[89]
    DIRECTION INPUT ;
    USE SIGNAL ;
    PORT
      LAYER M5 ;
        RECT  9.168 0 9.192 0.192 ;
    END
  END i[89]
  PIN i[8]
    DIRECTION INPUT ;
    USE SIGNAL ;
    PORT
      LAYER M3 ;
        RECT  2.808 0 2.826 0.144 ;
    END
  END i[8]
  PIN i[90]
    DIRECTION INPUT ;
    USE SIGNAL ;
    PORT
      LAYER M3 ;
        RECT  9.216 0 9.234 0.144 ;
    END
  END i[90]
  PIN i[91]
    DIRECTION INPUT ;
    USE SIGNAL ;
    PORT
      LAYER M5 ;
        RECT  9.312 0 9.336 0.192 ;
    END
  END i[91]
  PIN i[92]
    DIRECTION INPUT ;
    USE SIGNAL ;
    PORT
      LAYER M3 ;
        RECT  9.396 0 9.414 0.144 ;
    END
  END i[92]
  PIN i[93]
    DIRECTION INPUT ;
    USE SIGNAL ;
    PORT
      LAYER M5 ;
        RECT  9.456 0 9.48 0.192 ;
    END
  END i[93]
  PIN i[94]
    DIRECTION INPUT ;
    USE SIGNAL ;
    PORT
      LAYER M3 ;
        RECT  9.54 0 9.558 0.144 ;
    END
  END i[94]
  PIN i[95]
    DIRECTION INPUT ;
    USE SIGNAL ;
    PORT
      LAYER M5 ;
        RECT  9.6 0 9.624 0.192 ;
    END
  END i[95]
  PIN i[96]
    DIRECTION INPUT ;
    USE SIGNAL ;
    PORT
      LAYER M3 ;
        RECT  9.72 0 9.738 0.144 ;
    END
  END i[96]
  PIN i[97]
    DIRECTION INPUT ;
    USE SIGNAL ;
    PORT
      LAYER M5 ;
        RECT  9.792 0 9.816 0.192 ;
    END
  END i[97]
  PIN i[98]
    DIRECTION INPUT ;
    USE SIGNAL ;
    PORT
      LAYER M3 ;
        RECT  9.864 0 9.882 0.144 ;
    END
  END i[98]
  PIN i[99]
    DIRECTION INPUT ;
    USE SIGNAL ;
    PORT
      LAYER M5 ;
        RECT  9.936 0 9.96 0.192 ;
    END
  END i[99]
  PIN i[9]
    DIRECTION INPUT ;
    USE SIGNAL ;
    PORT
      LAYER M5 ;
        RECT  2.88 0 2.904 0.192 ;
    END
  END i[9]
  PIN o[0]
    DIRECTION OUTPUT ;
    USE SIGNAL ;
    PORT
      LAYER M3 ;
        RECT  2.196 17.136 2.214 17.28 ;
    END
  END o[0]
  PIN o[100]
    DIRECTION OUTPUT ;
    USE SIGNAL ;
    PORT
      LAYER M3 ;
        RECT  9.972 17.136 9.99 17.28 ;
    END
  END o[100]
  PIN o[101]
    DIRECTION OUTPUT ;
    USE SIGNAL ;
    PORT
      LAYER M5 ;
        RECT  10.08 17.088 10.104 17.28 ;
    END
  END o[101]
  PIN o[102]
    DIRECTION OUTPUT ;
    USE SIGNAL ;
    PORT
      LAYER M3 ;
        RECT  10.152 17.136 10.17 17.28 ;
    END
  END o[102]
  PIN o[103]
    DIRECTION OUTPUT ;
    USE SIGNAL ;
    PORT
      LAYER M5 ;
        RECT  10.224 17.088 10.248 17.28 ;
    END
  END o[103]
  PIN o[104]
    DIRECTION OUTPUT ;
    USE SIGNAL ;
    PORT
      LAYER M3 ;
        RECT  10.296 17.136 10.314 17.28 ;
    END
  END o[104]
  PIN o[105]
    DIRECTION OUTPUT ;
    USE SIGNAL ;
    PORT
      LAYER M5 ;
        RECT  10.368 17.088 10.392 17.28 ;
    END
  END o[105]
  PIN o[106]
    DIRECTION OUTPUT ;
    USE SIGNAL ;
    PORT
      LAYER M3 ;
        RECT  10.44 17.136 10.458 17.28 ;
    END
  END o[106]
  PIN o[107]
    DIRECTION OUTPUT ;
    USE SIGNAL ;
    PORT
      LAYER M5 ;
        RECT  10.512 17.088 10.536 17.28 ;
    END
  END o[107]
  PIN o[108]
    DIRECTION OUTPUT ;
    USE SIGNAL ;
    PORT
      LAYER M3 ;
        RECT  10.62 17.136 10.638 17.28 ;
    END
  END o[108]
  PIN o[109]
    DIRECTION OUTPUT ;
    USE SIGNAL ;
    PORT
      LAYER M5 ;
        RECT  10.704 17.088 10.728 17.28 ;
    END
  END o[109]
  PIN o[10]
    DIRECTION OUTPUT ;
    USE SIGNAL ;
    PORT
      LAYER M3 ;
        RECT  2.952 17.136 2.97 17.28 ;
    END
  END o[10]
  PIN o[110]
    DIRECTION OUTPUT ;
    USE SIGNAL ;
    PORT
      LAYER M3 ;
        RECT  10.764 17.136 10.782 17.28 ;
    END
  END o[110]
  PIN o[111]
    DIRECTION OUTPUT ;
    USE SIGNAL ;
    PORT
      LAYER M5 ;
        RECT  10.848 17.088 10.872 17.28 ;
    END
  END o[111]
  PIN o[112]
    DIRECTION OUTPUT ;
    USE SIGNAL ;
    PORT
      LAYER M3 ;
        RECT  10.908 17.136 10.926 17.28 ;
    END
  END o[112]
  PIN o[113]
    DIRECTION OUTPUT ;
    USE SIGNAL ;
    PORT
      LAYER M5 ;
        RECT  10.992 17.088 11.016 17.28 ;
    END
  END o[113]
  PIN o[114]
    DIRECTION OUTPUT ;
    USE SIGNAL ;
    PORT
      LAYER M3 ;
        RECT  11.088 17.136 11.106 17.28 ;
    END
  END o[114]
  PIN o[115]
    DIRECTION OUTPUT ;
    USE SIGNAL ;
    PORT
      LAYER M5 ;
        RECT  11.136 17.088 11.16 17.28 ;
    END
  END o[115]
  PIN o[116]
    DIRECTION OUTPUT ;
    USE SIGNAL ;
    PORT
      LAYER M3 ;
        RECT  11.232 17.136 11.25 17.28 ;
    END
  END o[116]
  PIN o[117]
    DIRECTION OUTPUT ;
    USE SIGNAL ;
    PORT
      LAYER M5 ;
        RECT  11.328 17.088 11.352 17.28 ;
    END
  END o[117]
  PIN o[118]
    DIRECTION OUTPUT ;
    USE SIGNAL ;
    PORT
      LAYER M3 ;
        RECT  11.376 17.136 11.394 17.28 ;
    END
  END o[118]
  PIN o[119]
    DIRECTION OUTPUT ;
    USE SIGNAL ;
    PORT
      LAYER M5 ;
        RECT  11.472 17.088 11.496 17.28 ;
    END
  END o[119]
  PIN o[11]
    DIRECTION OUTPUT ;
    USE SIGNAL ;
    PORT
      LAYER M5 ;
        RECT  3.024 17.088 3.048 17.28 ;
    END
  END o[11]
  PIN o[120]
    DIRECTION OUTPUT ;
    USE SIGNAL ;
    PORT
      LAYER M3 ;
        RECT  11.556 17.136 11.574 17.28 ;
    END
  END o[120]
  PIN o[121]
    DIRECTION OUTPUT ;
    USE SIGNAL ;
    PORT
      LAYER M5 ;
        RECT  11.616 17.088 11.64 17.28 ;
    END
  END o[121]
  PIN o[122]
    DIRECTION OUTPUT ;
    USE SIGNAL ;
    PORT
      LAYER M3 ;
        RECT  11.7 17.136 11.718 17.28 ;
    END
  END o[122]
  PIN o[123]
    DIRECTION OUTPUT ;
    USE SIGNAL ;
    PORT
      LAYER M5 ;
        RECT  11.76 17.088 11.784 17.28 ;
    END
  END o[123]
  PIN o[124]
    DIRECTION OUTPUT ;
    USE SIGNAL ;
    PORT
      LAYER M3 ;
        RECT  11.844 17.136 11.862 17.28 ;
    END
  END o[124]
  PIN o[125]
    DIRECTION OUTPUT ;
    USE SIGNAL ;
    PORT
      LAYER M5 ;
        RECT  11.952 17.088 11.976 17.28 ;
    END
  END o[125]
  PIN o[126]
    DIRECTION OUTPUT ;
    USE SIGNAL ;
    PORT
      LAYER M3 ;
        RECT  12.024 17.136 12.042 17.28 ;
    END
  END o[126]
  PIN o[127]
    DIRECTION OUTPUT ;
    USE SIGNAL ;
    PORT
      LAYER M5 ;
        RECT  12.096 17.088 12.12 17.28 ;
    END
  END o[127]
  PIN o[128]
    DIRECTION OUTPUT ;
    USE SIGNAL ;
    PORT
      LAYER M3 ;
        RECT  12.168 17.136 12.186 17.28 ;
    END
  END o[128]
  PIN o[129]
    DIRECTION OUTPUT ;
    USE SIGNAL ;
    PORT
      LAYER M5 ;
        RECT  12.24 17.088 12.264 17.28 ;
    END
  END o[129]
  PIN o[12]
    DIRECTION OUTPUT ;
    USE SIGNAL ;
    PORT
      LAYER M3 ;
        RECT  3.132 17.136 3.15 17.28 ;
    END
  END o[12]
  PIN o[130]
    DIRECTION OUTPUT ;
    USE SIGNAL ;
    PORT
      LAYER M3 ;
        RECT  12.312 17.136 12.33 17.28 ;
    END
  END o[130]
  PIN o[131]
    DIRECTION OUTPUT ;
    USE SIGNAL ;
    PORT
      LAYER M5 ;
        RECT  12.384 17.088 12.408 17.28 ;
    END
  END o[131]
  PIN o[132]
    DIRECTION OUTPUT ;
    USE SIGNAL ;
    PORT
      LAYER M3 ;
        RECT  12.492 17.136 12.51 17.28 ;
    END
  END o[132]
  PIN o[133]
    DIRECTION OUTPUT ;
    USE SIGNAL ;
    PORT
      LAYER M5 ;
        RECT  12.576 17.088 12.6 17.28 ;
    END
  END o[133]
  PIN o[134]
    DIRECTION OUTPUT ;
    USE SIGNAL ;
    PORT
      LAYER M3 ;
        RECT  12.636 17.136 12.654 17.28 ;
    END
  END o[134]
  PIN o[135]
    DIRECTION OUTPUT ;
    USE SIGNAL ;
    PORT
      LAYER M5 ;
        RECT  12.72 17.088 12.744 17.28 ;
    END
  END o[135]
  PIN o[136]
    DIRECTION OUTPUT ;
    USE SIGNAL ;
    PORT
      LAYER M3 ;
        RECT  12.78 17.136 12.798 17.28 ;
    END
  END o[136]
  PIN o[137]
    DIRECTION OUTPUT ;
    USE SIGNAL ;
    PORT
      LAYER M5 ;
        RECT  12.864 17.088 12.888 17.28 ;
    END
  END o[137]
  PIN o[138]
    DIRECTION OUTPUT ;
    USE SIGNAL ;
    PORT
      LAYER M5 ;
        RECT  13.008 17.088 13.032 17.28 ;
    END
  END o[138]
  PIN o[139]
    DIRECTION OUTPUT ;
    USE SIGNAL ;
    PORT
      LAYER M3 ;
        RECT  13.104 17.136 13.122 17.28 ;
    END
  END o[139]
  PIN o[13]
    DIRECTION OUTPUT ;
    USE SIGNAL ;
    PORT
      LAYER M5 ;
        RECT  3.216 17.088 3.24 17.28 ;
    END
  END o[13]
  PIN o[140]
    DIRECTION OUTPUT ;
    USE SIGNAL ;
    PORT
      LAYER M5 ;
        RECT  13.2 17.088 13.224 17.28 ;
    END
  END o[140]
  PIN o[141]
    DIRECTION OUTPUT ;
    USE SIGNAL ;
    PORT
      LAYER M3 ;
        RECT  13.248 17.136 13.266 17.28 ;
    END
  END o[141]
  PIN o[142]
    DIRECTION OUTPUT ;
    USE SIGNAL ;
    PORT
      LAYER M5 ;
        RECT  13.344 17.088 13.368 17.28 ;
    END
  END o[142]
  PIN o[143]
    DIRECTION OUTPUT ;
    USE SIGNAL ;
    PORT
      LAYER M3 ;
        RECT  13.428 17.136 13.446 17.28 ;
    END
  END o[143]
  PIN o[144]
    DIRECTION OUTPUT ;
    USE SIGNAL ;
    PORT
      LAYER M5 ;
        RECT  13.488 17.088 13.512 17.28 ;
    END
  END o[144]
  PIN o[145]
    DIRECTION OUTPUT ;
    USE SIGNAL ;
    PORT
      LAYER M3 ;
        RECT  13.572 17.136 13.59 17.28 ;
    END
  END o[145]
  PIN o[146]
    DIRECTION OUTPUT ;
    USE SIGNAL ;
    PORT
      LAYER M5 ;
        RECT  13.632 17.088 13.656 17.28 ;
    END
  END o[146]
  PIN o[147]
    DIRECTION OUTPUT ;
    USE SIGNAL ;
    PORT
      LAYER M3 ;
        RECT  13.716 17.136 13.734 17.28 ;
    END
  END o[147]
  PIN o[148]
    DIRECTION OUTPUT ;
    USE SIGNAL ;
    PORT
      LAYER M5 ;
        RECT  13.824 17.088 13.848 17.28 ;
    END
  END o[148]
  PIN o[149]
    DIRECTION OUTPUT ;
    USE SIGNAL ;
    PORT
      LAYER M3 ;
        RECT  13.896 17.136 13.914 17.28 ;
    END
  END o[149]
  PIN o[14]
    DIRECTION OUTPUT ;
    USE SIGNAL ;
    PORT
      LAYER M3 ;
        RECT  3.276 17.136 3.294 17.28 ;
    END
  END o[14]
  PIN o[150]
    DIRECTION OUTPUT ;
    USE SIGNAL ;
    PORT
      LAYER M5 ;
        RECT  13.968 17.088 13.992 17.28 ;
    END
  END o[150]
  PIN o[151]
    DIRECTION OUTPUT ;
    USE SIGNAL ;
    PORT
      LAYER M3 ;
        RECT  14.04 17.136 14.058 17.28 ;
    END
  END o[151]
  PIN o[152]
    DIRECTION OUTPUT ;
    USE SIGNAL ;
    PORT
      LAYER M5 ;
        RECT  14.112 17.088 14.136 17.28 ;
    END
  END o[152]
  PIN o[153]
    DIRECTION OUTPUT ;
    USE SIGNAL ;
    PORT
      LAYER M3 ;
        RECT  14.184 17.136 14.202 17.28 ;
    END
  END o[153]
  PIN o[154]
    DIRECTION OUTPUT ;
    USE SIGNAL ;
    PORT
      LAYER M5 ;
        RECT  14.256 17.088 14.28 17.28 ;
    END
  END o[154]
  PIN o[155]
    DIRECTION OUTPUT ;
    USE SIGNAL ;
    PORT
      LAYER M3 ;
        RECT  14.364 17.136 14.382 17.28 ;
    END
  END o[155]
  PIN o[156]
    DIRECTION OUTPUT ;
    USE SIGNAL ;
    PORT
      LAYER M5 ;
        RECT  14.448 17.088 14.472 17.28 ;
    END
  END o[156]
  PIN o[157]
    DIRECTION OUTPUT ;
    USE SIGNAL ;
    PORT
      LAYER M3 ;
        RECT  14.508 17.136 14.526 17.28 ;
    END
  END o[157]
  PIN o[158]
    DIRECTION OUTPUT ;
    USE SIGNAL ;
    PORT
      LAYER M5 ;
        RECT  14.592 17.088 14.616 17.28 ;
    END
  END o[158]
  PIN o[159]
    DIRECTION OUTPUT ;
    USE SIGNAL ;
    PORT
      LAYER M3 ;
        RECT  14.652 17.136 14.67 17.28 ;
    END
  END o[159]
  PIN o[15]
    DIRECTION OUTPUT ;
    USE SIGNAL ;
    PORT
      LAYER M5 ;
        RECT  3.36 17.088 3.384 17.28 ;
    END
  END o[15]
  PIN o[160]
    DIRECTION OUTPUT ;
    USE SIGNAL ;
    PORT
      LAYER M5 ;
        RECT  14.736 17.088 14.76 17.28 ;
    END
  END o[160]
  PIN o[161]
    DIRECTION OUTPUT ;
    USE SIGNAL ;
    PORT
      LAYER M3 ;
        RECT  14.832 17.136 14.85 17.28 ;
    END
  END o[161]
  PIN o[162]
    DIRECTION OUTPUT ;
    USE SIGNAL ;
    PORT
      LAYER M5 ;
        RECT  14.88 17.088 14.904 17.28 ;
    END
  END o[162]
  PIN o[163]
    DIRECTION OUTPUT ;
    USE SIGNAL ;
    PORT
      LAYER M3 ;
        RECT  14.976 17.136 14.994 17.28 ;
    END
  END o[163]
  PIN o[164]
    DIRECTION OUTPUT ;
    USE SIGNAL ;
    PORT
      LAYER M5 ;
        RECT  15.072 17.088 15.096 17.28 ;
    END
  END o[164]
  PIN o[165]
    DIRECTION OUTPUT ;
    USE SIGNAL ;
    PORT
      LAYER M3 ;
        RECT  15.12 17.136 15.138 17.28 ;
    END
  END o[165]
  PIN o[166]
    DIRECTION OUTPUT ;
    USE SIGNAL ;
    PORT
      LAYER M5 ;
        RECT  15.216 17.088 15.24 17.28 ;
    END
  END o[166]
  PIN o[167]
    DIRECTION OUTPUT ;
    USE SIGNAL ;
    PORT
      LAYER M3 ;
        RECT  15.3 17.136 15.318 17.28 ;
    END
    PORT
      LAYER M3 ;
        RECT  15.228 17.148 15.354 17.213 ;
    END
  END o[167]
  PIN o[168]
    DIRECTION OUTPUT ;
    USE SIGNAL ;
    PORT
      LAYER M5 ;
        RECT  15.36 17.088 15.384 17.28 ;
    END
  END o[168]
  PIN o[169]
    DIRECTION OUTPUT ;
    USE SIGNAL ;
    PORT
      LAYER M3 ;
        RECT  15.444 17.136 15.462 17.28 ;
    END
  END o[169]
  PIN o[16]
    DIRECTION OUTPUT ;
    USE SIGNAL ;
    PORT
      LAYER M3 ;
        RECT  3.42 17.136 3.438 17.28 ;
    END
  END o[16]
  PIN o[170]
    DIRECTION OUTPUT ;
    USE SIGNAL ;
    PORT
      LAYER M5 ;
        RECT  15.504 17.088 15.528 17.28 ;
    END
  END o[170]
  PIN o[171]
    DIRECTION OUTPUT ;
    USE SIGNAL ;
    PORT
      LAYER M3 ;
        RECT  15.588 17.136 15.606 17.28 ;
    END
  END o[171]
  PIN o[172]
    DIRECTION OUTPUT ;
    USE SIGNAL ;
    PORT
      LAYER M5 ;
        RECT  15.696 17.088 15.72 17.28 ;
    END
  END o[172]
  PIN o[173]
    DIRECTION OUTPUT ;
    USE SIGNAL ;
    PORT
      LAYER M3 ;
        RECT  15.768 17.136 15.786 17.28 ;
    END
  END o[173]
  PIN o[174]
    DIRECTION OUTPUT ;
    USE SIGNAL ;
    PORT
      LAYER M5 ;
        RECT  15.84 17.088 15.864 17.28 ;
    END
  END o[174]
  PIN o[175]
    DIRECTION OUTPUT ;
    USE SIGNAL ;
    PORT
      LAYER M3 ;
        RECT  15.912 17.136 15.93 17.28 ;
    END
  END o[175]
  PIN o[176]
    DIRECTION OUTPUT ;
    USE SIGNAL ;
    PORT
      LAYER M5 ;
        RECT  15.984 17.088 16.008 17.28 ;
    END
  END o[176]
  PIN o[177]
    DIRECTION OUTPUT ;
    USE SIGNAL ;
    PORT
      LAYER M3 ;
        RECT  16.056 17.136 16.074 17.28 ;
    END
  END o[177]
  PIN o[178]
    DIRECTION OUTPUT ;
    USE SIGNAL ;
    PORT
      LAYER M5 ;
        RECT  16.128 17.088 16.152 17.28 ;
    END
  END o[178]
  PIN o[179]
    DIRECTION OUTPUT ;
    USE SIGNAL ;
    PORT
      LAYER M3 ;
        RECT  16.236 17.136 16.254 17.28 ;
    END
  END o[179]
  PIN o[17]
    DIRECTION OUTPUT ;
    USE SIGNAL ;
    PORT
      LAYER M5 ;
        RECT  3.504 17.088 3.528 17.28 ;
    END
  END o[17]
  PIN o[180]
    DIRECTION OUTPUT ;
    USE SIGNAL ;
    PORT
      LAYER M5 ;
        RECT  16.32 17.088 16.344 17.28 ;
    END
  END o[180]
  PIN o[181]
    DIRECTION OUTPUT ;
    USE SIGNAL ;
    PORT
      LAYER M3 ;
        RECT  16.38 17.136 16.398 17.28 ;
    END
  END o[181]
  PIN o[182]
    DIRECTION OUTPUT ;
    USE SIGNAL ;
    PORT
      LAYER M5 ;
        RECT  16.464 17.088 16.488 17.28 ;
    END
  END o[182]
  PIN o[183]
    DIRECTION OUTPUT ;
    USE SIGNAL ;
    PORT
      LAYER M3 ;
        RECT  16.524 17.136 16.542 17.28 ;
    END
  END o[183]
  PIN o[184]
    DIRECTION OUTPUT ;
    USE SIGNAL ;
    PORT
      LAYER M5 ;
        RECT  16.608 17.088 16.632 17.28 ;
    END
  END o[184]
  PIN o[185]
    DIRECTION OUTPUT ;
    USE SIGNAL ;
    PORT
      LAYER M3 ;
        RECT  16.704 17.136 16.722 17.28 ;
    END
  END o[185]
  PIN o[186]
    DIRECTION OUTPUT ;
    USE SIGNAL ;
    PORT
      LAYER M5 ;
        RECT  16.752 17.088 16.776 17.28 ;
    END
  END o[186]
  PIN o[187]
    DIRECTION OUTPUT ;
    USE SIGNAL ;
    PORT
      LAYER M3 ;
        RECT  16.848 17.136 16.866 17.28 ;
    END
  END o[187]
  PIN o[188]
    DIRECTION OUTPUT ;
    USE SIGNAL ;
    PORT
      LAYER M5 ;
        RECT  16.944 17.088 16.968 17.28 ;
    END
  END o[188]
  PIN o[189]
    DIRECTION OUTPUT ;
    USE SIGNAL ;
    PORT
      LAYER M3 ;
        RECT  16.992 17.136 17.01 17.28 ;
    END
  END o[189]
  PIN o[18]
    DIRECTION OUTPUT ;
    USE SIGNAL ;
    PORT
      LAYER M3 ;
        RECT  3.6 17.136 3.618 17.28 ;
    END
  END o[18]
  PIN o[190]
    DIRECTION OUTPUT ;
    USE SIGNAL ;
    PORT
      LAYER M5 ;
        RECT  17.088 17.088 17.112 17.28 ;
    END
  END o[190]
  PIN o[191]
    DIRECTION OUTPUT ;
    USE SIGNAL ;
    PORT
      LAYER M3 ;
        RECT  17.172 17.136 17.19 17.28 ;
    END
  END o[191]
  PIN o[192]
    DIRECTION OUTPUT ;
    USE SIGNAL ;
    PORT
      LAYER M5 ;
        RECT  17.232 17.088 17.256 17.28 ;
    END
  END o[192]
  PIN o[193]
    DIRECTION OUTPUT ;
    USE SIGNAL ;
    PORT
      LAYER M3 ;
        RECT  17.316 17.136 17.334 17.28 ;
    END
  END o[193]
  PIN o[194]
    DIRECTION OUTPUT ;
    USE SIGNAL ;
    PORT
      LAYER M5 ;
        RECT  17.376 17.088 17.4 17.28 ;
    END
  END o[194]
  PIN o[195]
    DIRECTION OUTPUT ;
    USE SIGNAL ;
    PORT
      LAYER M3 ;
        RECT  17.46 17.136 17.478 17.28 ;
    END
  END o[195]
  PIN o[196]
    DIRECTION OUTPUT ;
    USE SIGNAL ;
    PORT
      LAYER M5 ;
        RECT  17.568 17.088 17.592 17.28 ;
    END
  END o[196]
  PIN o[197]
    DIRECTION OUTPUT ;
    USE SIGNAL ;
    PORT
      LAYER M3 ;
        RECT  17.64 17.136 17.658 17.28 ;
    END
  END o[197]
  PIN o[198]
    DIRECTION OUTPUT ;
    USE SIGNAL ;
    PORT
      LAYER M5 ;
        RECT  17.712 17.088 17.736 17.28 ;
    END
  END o[198]
  PIN o[199]
    DIRECTION OUTPUT ;
    USE SIGNAL ;
    PORT
      LAYER M3 ;
        RECT  17.784 17.136 17.802 17.28 ;
    END
  END o[199]
  PIN o[19]
    DIRECTION OUTPUT ;
    USE SIGNAL ;
    PORT
      LAYER M5 ;
        RECT  3.648 17.088 3.672 17.28 ;
    END
  END o[19]
  PIN o[1]
    DIRECTION OUTPUT ;
    USE SIGNAL ;
    PORT
      LAYER M5 ;
        RECT  2.256 17.088 2.28 17.28 ;
    END
  END o[1]
  PIN o[200]
    DIRECTION OUTPUT ;
    USE SIGNAL ;
    PORT
      LAYER M5 ;
        RECT  17.856 17.088 17.88 17.28 ;
    END
  END o[200]
  PIN o[201]
    DIRECTION OUTPUT ;
    USE SIGNAL ;
    PORT
      LAYER M3 ;
        RECT  17.928 17.136 17.946 17.28 ;
    END
  END o[201]
  PIN o[202]
    DIRECTION OUTPUT ;
    USE SIGNAL ;
    PORT
      LAYER M5 ;
        RECT  18 17.088 18.024 17.28 ;
    END
  END o[202]
  PIN o[203]
    DIRECTION OUTPUT ;
    USE SIGNAL ;
    PORT
      LAYER M3 ;
        RECT  18.108 17.136 18.126 17.28 ;
    END
  END o[203]
  PIN o[204]
    DIRECTION OUTPUT ;
    USE SIGNAL ;
    PORT
      LAYER M5 ;
        RECT  18.192 17.088 18.216 17.28 ;
    END
  END o[204]
  PIN o[205]
    DIRECTION OUTPUT ;
    USE SIGNAL ;
    PORT
      LAYER M3 ;
        RECT  18.252 17.136 18.27 17.28 ;
    END
  END o[205]
  PIN o[206]
    DIRECTION OUTPUT ;
    USE SIGNAL ;
    PORT
      LAYER M5 ;
        RECT  18.336 17.088 18.36 17.28 ;
    END
  END o[206]
  PIN o[207]
    DIRECTION OUTPUT ;
    USE SIGNAL ;
    PORT
      LAYER M3 ;
        RECT  18.396 17.136 18.414 17.28 ;
    END
  END o[207]
  PIN o[208]
    DIRECTION OUTPUT ;
    USE SIGNAL ;
    PORT
      LAYER M5 ;
        RECT  18.48 17.088 18.504 17.28 ;
    END
  END o[208]
  PIN o[209]
    DIRECTION OUTPUT ;
    USE SIGNAL ;
    PORT
      LAYER M3 ;
        RECT  18.576 17.136 18.594 17.28 ;
    END
  END o[209]
  PIN o[20]
    DIRECTION OUTPUT ;
    USE SIGNAL ;
    PORT
      LAYER M3 ;
        RECT  3.744 17.136 3.762 17.28 ;
    END
  END o[20]
  PIN o[210]
    DIRECTION OUTPUT ;
    USE SIGNAL ;
    PORT
      LAYER M5 ;
        RECT  18.624 17.088 18.648 17.28 ;
    END
  END o[210]
  PIN o[211]
    DIRECTION OUTPUT ;
    USE SIGNAL ;
    PORT
      LAYER M3 ;
        RECT  18.72 17.136 18.738 17.28 ;
    END
  END o[211]
  PIN o[212]
    DIRECTION OUTPUT ;
    USE SIGNAL ;
    PORT
      LAYER M5 ;
        RECT  18.816 17.088 18.84 17.28 ;
    END
  END o[212]
  PIN o[213]
    DIRECTION OUTPUT ;
    USE SIGNAL ;
    PORT
      LAYER M3 ;
        RECT  18.864 17.136 18.882 17.28 ;
    END
  END o[213]
  PIN o[214]
    DIRECTION OUTPUT ;
    USE SIGNAL ;
    PORT
      LAYER M5 ;
        RECT  18.96 17.088 18.984 17.28 ;
    END
  END o[214]
  PIN o[215]
    DIRECTION OUTPUT ;
    USE SIGNAL ;
    PORT
      LAYER M3 ;
        RECT  19.044 17.136 19.062 17.28 ;
    END
  END o[215]
  PIN o[216]
    DIRECTION OUTPUT ;
    USE SIGNAL ;
    PORT
      LAYER M5 ;
        RECT  19.104 17.088 19.128 17.28 ;
    END
  END o[216]
  PIN o[217]
    DIRECTION OUTPUT ;
    USE SIGNAL ;
    PORT
      LAYER M3 ;
        RECT  19.188 17.136 19.206 17.28 ;
    END
  END o[217]
  PIN o[218]
    DIRECTION OUTPUT ;
    USE SIGNAL ;
    PORT
      LAYER M5 ;
        RECT  19.248 17.088 19.272 17.28 ;
    END
  END o[218]
  PIN o[219]
    DIRECTION OUTPUT ;
    USE SIGNAL ;
    PORT
      LAYER M3 ;
        RECT  19.332 17.136 19.35 17.28 ;
    END
  END o[219]
  PIN o[21]
    DIRECTION OUTPUT ;
    USE SIGNAL ;
    PORT
      LAYER M5 ;
        RECT  3.84 17.088 3.864 17.28 ;
    END
  END o[21]
  PIN o[220]
    DIRECTION OUTPUT ;
    USE SIGNAL ;
    PORT
      LAYER M5 ;
        RECT  19.44 17.088 19.464 17.28 ;
    END
  END o[220]
  PIN o[221]
    DIRECTION OUTPUT ;
    USE SIGNAL ;
    PORT
      LAYER M3 ;
        RECT  19.512 17.136 19.53 17.28 ;
    END
  END o[221]
  PIN o[222]
    DIRECTION OUTPUT ;
    USE SIGNAL ;
    PORT
      LAYER M5 ;
        RECT  19.584 17.088 19.608 17.28 ;
    END
  END o[222]
  PIN o[223]
    DIRECTION OUTPUT ;
    USE SIGNAL ;
    PORT
      LAYER M3 ;
        RECT  19.656 17.136 19.674 17.28 ;
    END
  END o[223]
  PIN o[224]
    DIRECTION OUTPUT ;
    USE SIGNAL ;
    PORT
      LAYER M5 ;
        RECT  19.728 17.088 19.752 17.28 ;
    END
  END o[224]
  PIN o[225]
    DIRECTION OUTPUT ;
    USE SIGNAL ;
    PORT
      LAYER M3 ;
        RECT  19.8 17.136 19.818 17.28 ;
    END
  END o[225]
  PIN o[226]
    DIRECTION OUTPUT ;
    USE SIGNAL ;
    PORT
      LAYER M5 ;
        RECT  19.872 17.088 19.896 17.28 ;
    END
  END o[226]
  PIN o[227]
    DIRECTION OUTPUT ;
    USE SIGNAL ;
    PORT
      LAYER M3 ;
        RECT  19.98 17.136 19.998 17.28 ;
    END
  END o[227]
  PIN o[228]
    DIRECTION OUTPUT ;
    USE SIGNAL ;
    PORT
      LAYER M5 ;
        RECT  20.064 17.088 20.088 17.28 ;
    END
  END o[228]
  PIN o[229]
    DIRECTION OUTPUT ;
    USE SIGNAL ;
    PORT
      LAYER M3 ;
        RECT  20.124 17.136 20.142 17.28 ;
    END
  END o[229]
  PIN o[22]
    DIRECTION OUTPUT ;
    USE SIGNAL ;
    PORT
      LAYER M3 ;
        RECT  3.888 17.136 3.906 17.28 ;
    END
  END o[22]
  PIN o[230]
    DIRECTION OUTPUT ;
    USE SIGNAL ;
    PORT
      LAYER M5 ;
        RECT  20.208 17.088 20.232 17.28 ;
    END
  END o[230]
  PIN o[231]
    DIRECTION OUTPUT ;
    USE SIGNAL ;
    PORT
      LAYER M3 ;
        RECT  20.268 17.136 20.286 17.28 ;
    END
  END o[231]
  PIN o[232]
    DIRECTION OUTPUT ;
    USE SIGNAL ;
    PORT
      LAYER M5 ;
        RECT  20.352 17.088 20.376 17.28 ;
    END
  END o[232]
  PIN o[233]
    DIRECTION OUTPUT ;
    USE SIGNAL ;
    PORT
      LAYER M3 ;
        RECT  20.448 17.136 20.466 17.28 ;
    END
  END o[233]
  PIN o[234]
    DIRECTION OUTPUT ;
    USE SIGNAL ;
    PORT
      LAYER M5 ;
        RECT  20.496 17.088 20.52 17.28 ;
    END
  END o[234]
  PIN o[235]
    DIRECTION OUTPUT ;
    USE SIGNAL ;
    PORT
      LAYER M3 ;
        RECT  20.592 17.136 20.61 17.28 ;
    END
  END o[235]
  PIN o[236]
    DIRECTION OUTPUT ;
    USE SIGNAL ;
    PORT
      LAYER M5 ;
        RECT  20.688 17.088 20.712 17.28 ;
    END
  END o[236]
  PIN o[237]
    DIRECTION OUTPUT ;
    USE SIGNAL ;
    PORT
      LAYER M3 ;
        RECT  20.736 17.136 20.754 17.28 ;
    END
  END o[237]
  PIN o[238]
    DIRECTION OUTPUT ;
    USE SIGNAL ;
    PORT
      LAYER M5 ;
        RECT  20.832 17.088 20.856 17.28 ;
    END
  END o[238]
  PIN o[239]
    DIRECTION OUTPUT ;
    USE SIGNAL ;
    PORT
      LAYER M3 ;
        RECT  20.916 17.136 20.934 17.28 ;
    END
  END o[239]
  PIN o[23]
    DIRECTION OUTPUT ;
    USE SIGNAL ;
    PORT
      LAYER M5 ;
        RECT  3.984 17.088 4.008 17.28 ;
    END
  END o[23]
  PIN o[240]
    DIRECTION OUTPUT ;
    USE SIGNAL ;
    PORT
      LAYER M5 ;
        RECT  20.976 17.088 21 17.28 ;
    END
  END o[240]
  PIN o[241]
    DIRECTION OUTPUT ;
    USE SIGNAL ;
    PORT
      LAYER M3 ;
        RECT  21.06 17.136 21.078 17.28 ;
    END
  END o[241]
  PIN o[242]
    DIRECTION OUTPUT ;
    USE SIGNAL ;
    PORT
      LAYER M5 ;
        RECT  21.12 17.088 21.144 17.28 ;
    END
  END o[242]
  PIN o[243]
    DIRECTION OUTPUT ;
    USE SIGNAL ;
    PORT
      LAYER M3 ;
        RECT  21.204 17.136 21.222 17.28 ;
    END
  END o[243]
  PIN o[244]
    DIRECTION OUTPUT ;
    USE SIGNAL ;
    PORT
      LAYER M5 ;
        RECT  21.312 17.088 21.336 17.28 ;
    END
  END o[244]
  PIN o[245]
    DIRECTION OUTPUT ;
    USE SIGNAL ;
    PORT
      LAYER M3 ;
        RECT  21.384 17.136 21.402 17.28 ;
    END
  END o[245]
  PIN o[246]
    DIRECTION OUTPUT ;
    USE SIGNAL ;
    PORT
      LAYER M5 ;
        RECT  21.456 17.088 21.48 17.28 ;
    END
  END o[246]
  PIN o[247]
    DIRECTION OUTPUT ;
    USE SIGNAL ;
    PORT
      LAYER M3 ;
        RECT  21.528 17.136 21.546 17.28 ;
    END
  END o[247]
  PIN o[248]
    DIRECTION OUTPUT ;
    USE SIGNAL ;
    PORT
      LAYER M5 ;
        RECT  21.6 17.088 21.624 17.28 ;
    END
  END o[248]
  PIN o[249]
    DIRECTION OUTPUT ;
    USE SIGNAL ;
    PORT
      LAYER M3 ;
        RECT  21.672 17.136 21.69 17.28 ;
    END
  END o[249]
  PIN o[24]
    DIRECTION OUTPUT ;
    USE SIGNAL ;
    PORT
      LAYER M3 ;
        RECT  4.068 17.136 4.086 17.28 ;
    END
  END o[24]
  PIN o[250]
    DIRECTION OUTPUT ;
    USE SIGNAL ;
    PORT
      LAYER M5 ;
        RECT  21.744 17.088 21.768 17.28 ;
    END
  END o[250]
  PIN o[251]
    DIRECTION OUTPUT ;
    USE SIGNAL ;
    PORT
      LAYER M3 ;
        RECT  21.852 17.136 21.87 17.28 ;
    END
  END o[251]
  PIN o[252]
    DIRECTION OUTPUT ;
    USE SIGNAL ;
    PORT
      LAYER M5 ;
        RECT  21.936 17.088 21.96 17.28 ;
    END
  END o[252]
  PIN o[253]
    DIRECTION OUTPUT ;
    USE SIGNAL ;
    PORT
      LAYER M3 ;
        RECT  21.996 17.136 22.014 17.28 ;
    END
  END o[253]
  PIN o[254]
    DIRECTION OUTPUT ;
    USE SIGNAL ;
    PORT
      LAYER M5 ;
        RECT  22.08 17.088 22.104 17.28 ;
    END
  END o[254]
  PIN o[255]
    DIRECTION OUTPUT ;
    USE SIGNAL ;
    PORT
      LAYER M3 ;
        RECT  22.14 17.136 22.158 17.28 ;
    END
  END o[255]
  PIN o[256]
    DIRECTION OUTPUT ;
    USE SIGNAL ;
    PORT
      LAYER M5 ;
        RECT  22.224 17.088 22.248 17.28 ;
    END
  END o[256]
  PIN o[257]
    DIRECTION OUTPUT ;
    USE SIGNAL ;
    PORT
      LAYER M3 ;
        RECT  22.32 17.136 22.338 17.28 ;
    END
  END o[257]
  PIN o[258]
    DIRECTION OUTPUT ;
    USE SIGNAL ;
    PORT
      LAYER M5 ;
        RECT  22.368 17.088 22.392 17.28 ;
    END
  END o[258]
  PIN o[259]
    DIRECTION OUTPUT ;
    USE SIGNAL ;
    PORT
      LAYER M3 ;
        RECT  22.464 17.136 22.482 17.28 ;
    END
  END o[259]
  PIN o[25]
    DIRECTION OUTPUT ;
    USE SIGNAL ;
    PORT
      LAYER M5 ;
        RECT  4.128 17.088 4.152 17.28 ;
    END
  END o[25]
  PIN o[260]
    DIRECTION OUTPUT ;
    USE SIGNAL ;
    PORT
      LAYER M5 ;
        RECT  22.56 17.088 22.584 17.28 ;
    END
  END o[260]
  PIN o[261]
    DIRECTION OUTPUT ;
    USE SIGNAL ;
    PORT
      LAYER M3 ;
        RECT  22.608 17.136 22.626 17.28 ;
    END
  END o[261]
  PIN o[262]
    DIRECTION OUTPUT ;
    USE SIGNAL ;
    PORT
      LAYER M5 ;
        RECT  22.704 17.088 22.728 17.28 ;
    END
  END o[262]
  PIN o[263]
    DIRECTION OUTPUT ;
    USE SIGNAL ;
    PORT
      LAYER M3 ;
        RECT  22.788 17.136 22.806 17.28 ;
    END
  END o[263]
  PIN o[264]
    DIRECTION OUTPUT ;
    USE SIGNAL ;
    PORT
      LAYER M5 ;
        RECT  22.848 17.088 22.872 17.28 ;
    END
  END o[264]
  PIN o[265]
    DIRECTION OUTPUT ;
    USE SIGNAL ;
    PORT
      LAYER M3 ;
        RECT  22.932 17.136 22.95 17.28 ;
    END
  END o[265]
  PIN o[266]
    DIRECTION OUTPUT ;
    USE SIGNAL ;
    PORT
      LAYER M5 ;
        RECT  22.992 17.088 23.016 17.28 ;
    END
  END o[266]
  PIN o[267]
    DIRECTION OUTPUT ;
    USE SIGNAL ;
    PORT
      LAYER M3 ;
        RECT  23.076 17.136 23.094 17.28 ;
    END
  END o[267]
  PIN o[268]
    DIRECTION OUTPUT ;
    USE SIGNAL ;
    PORT
      LAYER M5 ;
        RECT  23.184 17.088 23.208 17.28 ;
    END
  END o[268]
  PIN o[269]
    DIRECTION OUTPUT ;
    USE SIGNAL ;
    PORT
      LAYER M3 ;
        RECT  23.256 17.136 23.274 17.28 ;
    END
  END o[269]
  PIN o[26]
    DIRECTION OUTPUT ;
    USE SIGNAL ;
    PORT
      LAYER M3 ;
        RECT  4.212 17.136 4.23 17.28 ;
    END
  END o[26]
  PIN o[270]
    DIRECTION OUTPUT ;
    USE SIGNAL ;
    PORT
      LAYER M5 ;
        RECT  23.328 17.088 23.352 17.28 ;
    END
  END o[270]
  PIN o[271]
    DIRECTION OUTPUT ;
    USE SIGNAL ;
    PORT
      LAYER M3 ;
        RECT  23.4 17.136 23.418 17.28 ;
    END
  END o[271]
  PIN o[272]
    DIRECTION OUTPUT ;
    USE SIGNAL ;
    PORT
      LAYER M5 ;
        RECT  23.472 17.088 23.496 17.28 ;
    END
  END o[272]
  PIN o[273]
    DIRECTION OUTPUT ;
    USE SIGNAL ;
    PORT
      LAYER M3 ;
        RECT  23.544 17.136 23.562 17.28 ;
    END
  END o[273]
  PIN o[274]
    DIRECTION OUTPUT ;
    USE SIGNAL ;
    PORT
      LAYER M5 ;
        RECT  23.616 17.088 23.64 17.28 ;
    END
  END o[274]
  PIN o[275]
    DIRECTION OUTPUT ;
    USE SIGNAL ;
    PORT
      LAYER M3 ;
        RECT  23.724 17.136 23.742 17.28 ;
    END
  END o[275]
  PIN o[27]
    DIRECTION OUTPUT ;
    USE SIGNAL ;
    PORT
      LAYER M5 ;
        RECT  4.272 17.088 4.296 17.28 ;
    END
  END o[27]
  PIN o[28]
    DIRECTION OUTPUT ;
    USE SIGNAL ;
    PORT
      LAYER M3 ;
        RECT  4.356 17.136 4.374 17.28 ;
    END
  END o[28]
  PIN o[29]
    DIRECTION OUTPUT ;
    USE SIGNAL ;
    PORT
      LAYER M5 ;
        RECT  4.464 17.088 4.488 17.28 ;
    END
  END o[29]
  PIN o[2]
    DIRECTION OUTPUT ;
    USE SIGNAL ;
    PORT
      LAYER M3 ;
        RECT  2.34 17.136 2.358 17.28 ;
    END
  END o[2]
  PIN o[30]
    DIRECTION OUTPUT ;
    USE SIGNAL ;
    PORT
      LAYER M3 ;
        RECT  4.536 17.136 4.554 17.28 ;
    END
  END o[30]
  PIN o[31]
    DIRECTION OUTPUT ;
    USE SIGNAL ;
    PORT
      LAYER M5 ;
        RECT  4.608 17.088 4.632 17.28 ;
    END
  END o[31]
  PIN o[32]
    DIRECTION OUTPUT ;
    USE SIGNAL ;
    PORT
      LAYER M3 ;
        RECT  4.68 17.136 4.698 17.28 ;
    END
  END o[32]
  PIN o[33]
    DIRECTION OUTPUT ;
    USE SIGNAL ;
    PORT
      LAYER M5 ;
        RECT  4.752 17.088 4.776 17.28 ;
    END
  END o[33]
  PIN o[34]
    DIRECTION OUTPUT ;
    USE SIGNAL ;
    PORT
      LAYER M3 ;
        RECT  4.824 17.136 4.842 17.28 ;
    END
  END o[34]
  PIN o[35]
    DIRECTION OUTPUT ;
    USE SIGNAL ;
    PORT
      LAYER M5 ;
        RECT  4.896 17.088 4.92 17.28 ;
    END
  END o[35]
  PIN o[36]
    DIRECTION OUTPUT ;
    USE SIGNAL ;
    PORT
      LAYER M3 ;
        RECT  5.004 17.136 5.022 17.28 ;
    END
  END o[36]
  PIN o[37]
    DIRECTION OUTPUT ;
    USE SIGNAL ;
    PORT
      LAYER M5 ;
        RECT  5.088 17.088 5.112 17.28 ;
    END
  END o[37]
  PIN o[38]
    DIRECTION OUTPUT ;
    USE SIGNAL ;
    PORT
      LAYER M3 ;
        RECT  5.148 17.136 5.166 17.28 ;
    END
  END o[38]
  PIN o[39]
    DIRECTION OUTPUT ;
    USE SIGNAL ;
    PORT
      LAYER M5 ;
        RECT  5.232 17.088 5.256 17.28 ;
    END
  END o[39]
  PIN o[3]
    DIRECTION OUTPUT ;
    USE SIGNAL ;
    PORT
      LAYER M5 ;
        RECT  2.4 17.088 2.424 17.28 ;
    END
  END o[3]
  PIN o[40]
    DIRECTION OUTPUT ;
    USE SIGNAL ;
    PORT
      LAYER M3 ;
        RECT  5.292 17.136 5.31 17.28 ;
    END
  END o[40]
  PIN o[41]
    DIRECTION OUTPUT ;
    USE SIGNAL ;
    PORT
      LAYER M5 ;
        RECT  5.376 17.088 5.4 17.28 ;
    END
  END o[41]
  PIN o[42]
    DIRECTION OUTPUT ;
    USE SIGNAL ;
    PORT
      LAYER M3 ;
        RECT  5.472 17.136 5.49 17.28 ;
    END
  END o[42]
  PIN o[43]
    DIRECTION OUTPUT ;
    USE SIGNAL ;
    PORT
      LAYER M5 ;
        RECT  5.52 17.088 5.544 17.28 ;
    END
  END o[43]
  PIN o[44]
    DIRECTION OUTPUT ;
    USE SIGNAL ;
    PORT
      LAYER M3 ;
        RECT  5.616 17.136 5.634 17.28 ;
    END
  END o[44]
  PIN o[45]
    DIRECTION OUTPUT ;
    USE SIGNAL ;
    PORT
      LAYER M5 ;
        RECT  5.712 17.088 5.736 17.28 ;
    END
  END o[45]
  PIN o[46]
    DIRECTION OUTPUT ;
    USE SIGNAL ;
    PORT
      LAYER M3 ;
        RECT  5.76 17.136 5.778 17.28 ;
    END
  END o[46]
  PIN o[47]
    DIRECTION OUTPUT ;
    USE SIGNAL ;
    PORT
      LAYER M5 ;
        RECT  5.856 17.088 5.88 17.28 ;
    END
  END o[47]
  PIN o[48]
    DIRECTION OUTPUT ;
    USE SIGNAL ;
    PORT
      LAYER M3 ;
        RECT  5.94 17.136 5.958 17.28 ;
    END
  END o[48]
  PIN o[49]
    DIRECTION OUTPUT ;
    USE SIGNAL ;
    PORT
      LAYER M5 ;
        RECT  6 17.088 6.024 17.28 ;
    END
  END o[49]
  PIN o[4]
    DIRECTION OUTPUT ;
    USE SIGNAL ;
    PORT
      LAYER M3 ;
        RECT  2.484 17.136 2.502 17.28 ;
    END
  END o[4]
  PIN o[50]
    DIRECTION OUTPUT ;
    USE SIGNAL ;
    PORT
      LAYER M3 ;
        RECT  6.084 17.136 6.102 17.28 ;
    END
  END o[50]
  PIN o[51]
    DIRECTION OUTPUT ;
    USE SIGNAL ;
    PORT
      LAYER M5 ;
        RECT  6.144 17.088 6.168 17.28 ;
    END
  END o[51]
  PIN o[52]
    DIRECTION OUTPUT ;
    USE SIGNAL ;
    PORT
      LAYER M3 ;
        RECT  6.228 17.136 6.246 17.28 ;
    END
  END o[52]
  PIN o[53]
    DIRECTION OUTPUT ;
    USE SIGNAL ;
    PORT
      LAYER M5 ;
        RECT  6.336 17.088 6.36 17.28 ;
    END
  END o[53]
  PIN o[54]
    DIRECTION OUTPUT ;
    USE SIGNAL ;
    PORT
      LAYER M3 ;
        RECT  6.408 17.136 6.426 17.28 ;
    END
  END o[54]
  PIN o[55]
    DIRECTION OUTPUT ;
    USE SIGNAL ;
    PORT
      LAYER M5 ;
        RECT  6.48 17.088 6.504 17.28 ;
    END
  END o[55]
  PIN o[56]
    DIRECTION OUTPUT ;
    USE SIGNAL ;
    PORT
      LAYER M3 ;
        RECT  6.552 17.136 6.57 17.28 ;
    END
  END o[56]
  PIN o[57]
    DIRECTION OUTPUT ;
    USE SIGNAL ;
    PORT
      LAYER M5 ;
        RECT  6.624 17.088 6.648 17.28 ;
    END
  END o[57]
  PIN o[58]
    DIRECTION OUTPUT ;
    USE SIGNAL ;
    PORT
      LAYER M3 ;
        RECT  6.696 17.136 6.714 17.28 ;
    END
  END o[58]
  PIN o[59]
    DIRECTION OUTPUT ;
    USE SIGNAL ;
    PORT
      LAYER M5 ;
        RECT  6.768 17.088 6.792 17.28 ;
    END
  END o[59]
  PIN o[5]
    DIRECTION OUTPUT ;
    USE SIGNAL ;
    PORT
      LAYER M5 ;
        RECT  2.592 17.088 2.616 17.28 ;
    END
  END o[5]
  PIN o[60]
    DIRECTION OUTPUT ;
    USE SIGNAL ;
    PORT
      LAYER M3 ;
        RECT  6.876 17.136 6.894 17.28 ;
    END
  END o[60]
  PIN o[61]
    DIRECTION OUTPUT ;
    USE SIGNAL ;
    PORT
      LAYER M5 ;
        RECT  6.96 17.088 6.984 17.28 ;
    END
  END o[61]
  PIN o[62]
    DIRECTION OUTPUT ;
    USE SIGNAL ;
    PORT
      LAYER M3 ;
        RECT  7.02 17.136 7.038 17.28 ;
    END
  END o[62]
  PIN o[63]
    DIRECTION OUTPUT ;
    USE SIGNAL ;
    PORT
      LAYER M5 ;
        RECT  7.104 17.088 7.128 17.28 ;
    END
  END o[63]
  PIN o[64]
    DIRECTION OUTPUT ;
    USE SIGNAL ;
    PORT
      LAYER M3 ;
        RECT  7.164 17.136 7.182 17.28 ;
    END
  END o[64]
  PIN o[65]
    DIRECTION OUTPUT ;
    USE SIGNAL ;
    PORT
      LAYER M5 ;
        RECT  7.248 17.088 7.272 17.28 ;
    END
  END o[65]
  PIN o[66]
    DIRECTION OUTPUT ;
    USE SIGNAL ;
    PORT
      LAYER M3 ;
        RECT  7.344 17.136 7.362 17.28 ;
    END
  END o[66]
  PIN o[67]
    DIRECTION OUTPUT ;
    USE SIGNAL ;
    PORT
      LAYER M5 ;
        RECT  7.392 17.088 7.416 17.28 ;
    END
  END o[67]
  PIN o[68]
    DIRECTION OUTPUT ;
    USE SIGNAL ;
    PORT
      LAYER M3 ;
        RECT  7.488 17.136 7.506 17.28 ;
    END
  END o[68]
  PIN o[69]
    DIRECTION OUTPUT ;
    USE SIGNAL ;
    PORT
      LAYER M5 ;
        RECT  7.584 17.088 7.608 17.28 ;
    END
  END o[69]
  PIN o[6]
    DIRECTION OUTPUT ;
    USE SIGNAL ;
    PORT
      LAYER M3 ;
        RECT  2.664 17.136 2.682 17.28 ;
    END
  END o[6]
  PIN o[70]
    DIRECTION OUTPUT ;
    USE SIGNAL ;
    PORT
      LAYER M3 ;
        RECT  7.632 17.136 7.65 17.28 ;
    END
  END o[70]
  PIN o[71]
    DIRECTION OUTPUT ;
    USE SIGNAL ;
    PORT
      LAYER M5 ;
        RECT  7.728 17.088 7.752 17.28 ;
    END
  END o[71]
  PIN o[72]
    DIRECTION OUTPUT ;
    USE SIGNAL ;
    PORT
      LAYER M3 ;
        RECT  7.812 17.136 7.83 17.28 ;
    END
  END o[72]
  PIN o[73]
    DIRECTION OUTPUT ;
    USE SIGNAL ;
    PORT
      LAYER M5 ;
        RECT  7.872 17.088 7.896 17.28 ;
    END
  END o[73]
  PIN o[74]
    DIRECTION OUTPUT ;
    USE SIGNAL ;
    PORT
      LAYER M3 ;
        RECT  7.956 17.136 7.974 17.28 ;
    END
  END o[74]
  PIN o[75]
    DIRECTION OUTPUT ;
    USE SIGNAL ;
    PORT
      LAYER M5 ;
        RECT  8.016 17.088 8.04 17.28 ;
    END
  END o[75]
  PIN o[76]
    DIRECTION OUTPUT ;
    USE SIGNAL ;
    PORT
      LAYER M3 ;
        RECT  8.1 17.136 8.118 17.28 ;
    END
  END o[76]
  PIN o[77]
    DIRECTION OUTPUT ;
    USE SIGNAL ;
    PORT
      LAYER M5 ;
        RECT  8.208 17.088 8.232 17.28 ;
    END
  END o[77]
  PIN o[78]
    DIRECTION OUTPUT ;
    USE SIGNAL ;
    PORT
      LAYER M3 ;
        RECT  8.28 17.136 8.298 17.28 ;
    END
  END o[78]
  PIN o[79]
    DIRECTION OUTPUT ;
    USE SIGNAL ;
    PORT
      LAYER M5 ;
        RECT  8.352 17.088 8.376 17.28 ;
    END
  END o[79]
  PIN o[7]
    DIRECTION OUTPUT ;
    USE SIGNAL ;
    PORT
      LAYER M5 ;
        RECT  2.736 17.088 2.76 17.28 ;
    END
  END o[7]
  PIN o[80]
    DIRECTION OUTPUT ;
    USE SIGNAL ;
    PORT
      LAYER M3 ;
        RECT  8.424 17.136 8.442 17.28 ;
    END
  END o[80]
  PIN o[81]
    DIRECTION OUTPUT ;
    USE SIGNAL ;
    PORT
      LAYER M5 ;
        RECT  8.496 17.088 8.52 17.28 ;
    END
  END o[81]
  PIN o[82]
    DIRECTION OUTPUT ;
    USE SIGNAL ;
    PORT
      LAYER M3 ;
        RECT  8.568 17.136 8.586 17.28 ;
    END
  END o[82]
  PIN o[83]
    DIRECTION OUTPUT ;
    USE SIGNAL ;
    PORT
      LAYER M5 ;
        RECT  8.64 17.088 8.664 17.28 ;
    END
  END o[83]
  PIN o[84]
    DIRECTION OUTPUT ;
    USE SIGNAL ;
    PORT
      LAYER M3 ;
        RECT  8.748 17.136 8.766 17.28 ;
    END
  END o[84]
  PIN o[85]
    DIRECTION OUTPUT ;
    USE SIGNAL ;
    PORT
      LAYER M5 ;
        RECT  8.832 17.088 8.856 17.28 ;
    END
  END o[85]
  PIN o[86]
    DIRECTION OUTPUT ;
    USE SIGNAL ;
    PORT
      LAYER M3 ;
        RECT  8.892 17.136 8.91 17.28 ;
    END
  END o[86]
  PIN o[87]
    DIRECTION OUTPUT ;
    USE SIGNAL ;
    PORT
      LAYER M5 ;
        RECT  8.976 17.088 9 17.28 ;
    END
  END o[87]
  PIN o[88]
    DIRECTION OUTPUT ;
    USE SIGNAL ;
    PORT
      LAYER M3 ;
        RECT  9.036 17.136 9.054 17.28 ;
    END
  END o[88]
  PIN o[89]
    DIRECTION OUTPUT ;
    USE SIGNAL ;
    PORT
      LAYER M5 ;
        RECT  9.12 17.088 9.144 17.28 ;
    END
  END o[89]
  PIN o[8]
    DIRECTION OUTPUT ;
    USE SIGNAL ;
    PORT
      LAYER M3 ;
        RECT  2.808 17.136 2.826 17.28 ;
    END
  END o[8]
  PIN o[90]
    DIRECTION OUTPUT ;
    USE SIGNAL ;
    PORT
      LAYER M3 ;
        RECT  9.216 17.136 9.234 17.28 ;
    END
  END o[90]
  PIN o[91]
    DIRECTION OUTPUT ;
    USE SIGNAL ;
    PORT
      LAYER M5 ;
        RECT  9.264 17.088 9.288 17.28 ;
    END
  END o[91]
  PIN o[92]
    DIRECTION OUTPUT ;
    USE SIGNAL ;
    PORT
      LAYER M3 ;
        RECT  9.36 17.136 9.378 17.28 ;
    END
  END o[92]
  PIN o[93]
    DIRECTION OUTPUT ;
    USE SIGNAL ;
    PORT
      LAYER M5 ;
        RECT  9.456 17.088 9.48 17.28 ;
    END
  END o[93]
  PIN o[94]
    DIRECTION OUTPUT ;
    USE SIGNAL ;
    PORT
      LAYER M3 ;
        RECT  9.504 17.136 9.522 17.28 ;
    END
  END o[94]
  PIN o[95]
    DIRECTION OUTPUT ;
    USE SIGNAL ;
    PORT
      LAYER M5 ;
        RECT  9.6 17.088 9.624 17.28 ;
    END
  END o[95]
  PIN o[96]
    DIRECTION OUTPUT ;
    USE SIGNAL ;
    PORT
      LAYER M3 ;
        RECT  9.684 17.136 9.702 17.28 ;
    END
  END o[96]
  PIN o[97]
    DIRECTION OUTPUT ;
    USE SIGNAL ;
    PORT
      LAYER M5 ;
        RECT  9.744 17.088 9.768 17.28 ;
    END
  END o[97]
  PIN o[98]
    DIRECTION OUTPUT ;
    USE SIGNAL ;
    PORT
      LAYER M3 ;
        RECT  9.828 17.136 9.846 17.28 ;
    END
  END o[98]
  PIN o[99]
    DIRECTION OUTPUT ;
    USE SIGNAL ;
    PORT
      LAYER M5 ;
        RECT  9.888 17.088 9.912 17.28 ;
    END
  END o[99]
  PIN o[9]
    DIRECTION OUTPUT ;
    USE SIGNAL ;
    PORT
      LAYER M5 ;
        RECT  2.88 17.088 2.904 17.28 ;
    END
  END o[9]
  PIN rs
    DIRECTION INPUT ;
    USE SIGNAL ;
    PORT
      LAYER M4 ;
        RECT  25.728 11.904 25.92 11.928 ;
    END
    PORT
      LAYER M4 ;
        RECT  24.947 11.904 25.74 11.928 ;
    END
  END rs
  PIN VDD
    DIRECTION INOUT ;
    USE POWER ;
    PORT
      LAYER M5 ;
        RECT  21.492 2.151 21.612 15.129 ;
        RECT  18.792 2.151 18.912 15.129 ;
        RECT  16.092 2.151 16.212 15.129 ;
        RECT  13.392 2.151 13.512 15.129 ;
        RECT  10.692 2.151 10.812 15.129 ;
        RECT  7.992 2.151 8.112 15.129 ;
        RECT  5.292 2.151 5.412 15.129 ;
        RECT  2.592 2.151 2.712 15.129 ;
    END
  END VDD
  PIN VSS
    DIRECTION INOUT ;
    USE GROUND ;
    PORT
      LAYER M5 ;
        RECT  21.3 2.137 21.42 15.143 ;
        RECT  18.6 2.137 18.72 15.143 ;
        RECT  15.9 2.137 16.02 15.143 ;
        RECT  13.2 2.137 13.32 15.143 ;
        RECT  10.5 2.137 10.62 15.143 ;
        RECT  7.8 2.137 7.92 15.143 ;
        RECT  5.1 2.137 5.22 15.143 ;
        RECT  2.4 2.137 2.52 15.143 ;
    END
  END VSS
  # OT_OBS_CLOSED layer=M5 d_um=1.536 added=14
  OBS
    LAYER RVTN ;
     RECT  2.16 2.16 23.76 2.295 ;
     RECT  2.16 2.565 23.76 2.835 ;
     RECT  2.16 3.105 23.76 3.375 ;
     RECT  2.16 3.645 23.76 3.915 ;
     RECT  2.16 4.185 23.76 4.455 ;
     RECT  2.16 4.725 23.76 4.995 ;
     RECT  2.16 5.265 23.76 5.535 ;
     RECT  2.16 5.805 23.76 6.075 ;
     RECT  2.16 6.345 23.76 6.615 ;
     RECT  2.16 6.885 23.76 7.155 ;
     RECT  2.16 7.425 23.76 7.695 ;
     RECT  2.16 7.965 23.76 8.235 ;
     RECT  2.16 8.505 23.76 8.775 ;
     RECT  2.16 9.045 23.76 9.315 ;
     RECT  2.16 9.585 23.76 9.855 ;
     RECT  2.16 10.125 23.76 10.395 ;
     RECT  2.16 10.665 23.76 10.935 ;
     RECT  2.16 11.205 23.76 11.475 ;
     RECT  2.16 11.745 23.76 12.015 ;
     RECT  2.16 12.285 23.76 12.555 ;
     RECT  2.16 12.825 23.76 13.095 ;
     RECT  2.16 13.365 23.76 13.635 ;
     RECT  2.16 13.905 23.76 14.175 ;
     RECT  2.16 14.445 23.76 14.715 ;
     RECT  2.16 14.985 23.76 15.12 ;
    LAYER RVTP ;
     RECT  2.16 2.295 23.76 2.565 ;
     RECT  2.16 2.835 23.76 3.105 ;
     RECT  2.16 3.375 23.76 3.645 ;
     RECT  2.16 3.915 23.76 4.185 ;
     RECT  2.16 4.455 23.76 4.725 ;
     RECT  2.16 4.995 23.76 5.265 ;
     RECT  2.16 5.535 23.76 5.805 ;
     RECT  2.16 6.075 23.76 6.345 ;
     RECT  2.16 6.615 23.76 6.885 ;
     RECT  2.16 7.155 23.76 7.425 ;
     RECT  2.16 7.695 23.76 7.965 ;
     RECT  2.16 8.235 23.76 8.505 ;
     RECT  2.16 8.775 23.76 9.045 ;
     RECT  2.16 9.315 23.76 9.585 ;
     RECT  2.16 9.855 23.76 10.125 ;
     RECT  2.16 10.395 23.76 10.665 ;
     RECT  2.16 10.935 23.76 11.205 ;
     RECT  2.16 11.475 23.76 11.745 ;
     RECT  2.16 12.015 23.76 12.285 ;
     RECT  2.16 12.555 23.76 12.825 ;
     RECT  2.16 13.095 23.76 13.365 ;
     RECT  2.16 13.635 23.76 13.905 ;
     RECT  2.16 14.175 23.76 14.445 ;
     RECT  2.16 14.715 23.76 14.985 ;
    LAYER M1 ;
     RECT  2.16 2.151 23.76 15.129 ;
    LAYER M2 ;
     RECT  0.355 8.01 0.427 8.028 ;
     RECT  0.427 7.704 0.463 8.028 ;
     RECT  0.787 6.696 0.823 6.714 ;
     RECT  0.463 7.506 0.823 8.028 ;
     RECT  0.823 2.844 0.859 2.862 ;
     RECT  0.859 2.34 1.003 2.862 ;
     RECT  0.967 10.404 1.003 10.422 ;
     RECT  0.859 5.121 1.039 5.139 ;
     RECT  1.003 9.756 1.039 10.422 ;
     RECT  1.003 2.34 1.111 2.934 ;
     RECT  1.039 5.121 1.111 5.634 ;
     RECT  0.283 13.446 1.111 13.464 ;
     RECT  1.111 13.374 1.147 13.464 ;
     RECT  1.147 13.176 1.219 13.464 ;
     RECT  0.823 6.696 1.255 8.028 ;
     RECT  1.111 2.106 1.291 2.934 ;
     RECT  0.499 3.96 1.291 3.978 ;
     RECT  1.219 13.104 1.319 13.464 ;
     RECT  1.039 9.756 1.327 10.728 ;
     RECT  1.471 0.882 1.543 0.9 ;
     RECT  1.111 5.076 1.579 5.634 ;
     RECT  0.499 11.484 1.579 11.502 ;
     RECT  1.075 12.294 1.579 12.312 ;
     RECT  1.579 5.004 1.615 5.634 ;
     RECT  1.615 5.004 1.651 5.679 ;
     RECT  1.255 6.624 1.651 8.028 ;
     RECT  1.291 2.106 1.687 3.978 ;
     RECT  1.651 5.004 1.687 8.028 ;
     RECT  1.687 2.106 1.723 8.028 ;
     RECT  1.327 9.054 1.723 10.728 ;
     RECT  1.579 11.484 1.975 12.312 ;
     RECT  1.543 0.846 2.119 0.9 ;
     RECT  1.723 2.106 2.119 10.728 ;
     RECT  1.975 11.484 2.119 12.618 ;
     RECT  2.119 2.106 2.16 12.618 ;
     RECT  1.319 13.374 2.16 13.464 ;
     RECT  1.219 14.256 2.16 14.274 ;
     RECT  2.16 2.106 2.227 15.129 ;
     RECT  2.227 1.998 2.335 15.129 ;
     RECT  2.335 1.728 2.479 15.129 ;
     RECT  2.479 1.728 2.579 15.21 ;
     RECT  2.119 0.144 2.759 0.9 ;
     RECT  2.579 1.728 2.831 15.129 ;
     RECT  2.759 0.846 2.983 0.9 ;
     RECT  2.983 0.846 3.227 1.242 ;
     RECT  2.831 1.998 3.919 15.129 ;
     RECT  3.227 0.846 4.063 0.9 ;
     RECT  3.919 1.728 4.199 15.129 ;
     RECT  4.199 1.998 4.207 15.129 ;
     RECT  4.207 1.998 4.343 15.516 ;
     RECT  4.063 0.144 4.423 0.9 ;
     RECT  4.423 0.144 4.523 1.17 ;
     RECT  4.343 1.998 5.143 15.129 ;
     RECT  5.143 1.998 5.179 15.21 ;
     RECT  5.179 1.926 5.387 15.21 ;
     RECT  4.523 0.144 5.431 0.9 ;
     RECT  5.431 0.144 5.531 1.17 ;
     RECT  5.387 2.106 5.935 15.21 ;
     RECT  5.935 2.106 6.035 15.282 ;
     RECT  5.531 0.144 6.331 0.864 ;
     RECT  6.035 2.106 6.871 15.21 ;
     RECT  6.331 0.144 7.223 1.17 ;
     RECT  6.871 2.106 7.663 15.246 ;
     RECT  7.223 0.144 7.951 0.864 ;
     RECT  7.663 2.106 7.979 15.282 ;
     RECT  7.979 2.106 8.123 15.129 ;
     RECT  7.951 0.036 8.203 0.864 ;
     RECT  8.203 0.036 8.303 1.242 ;
     RECT  8.303 0.036 8.375 1.17 ;
     RECT  8.419 16.074 8.519 16.092 ;
     RECT  8.375 0.036 9.419 0.864 ;
     RECT  8.123 2.151 9.643 15.129 ;
     RECT  9.643 2.106 9.931 15.129 ;
     RECT  9.419 0.036 10.031 0.279 ;
     RECT  9.931 2.106 10.175 15.246 ;
     RECT  10.175 2.106 10.291 15.21 ;
     RECT  10.291 1.998 10.427 15.21 ;
     RECT  10.031 0.036 10.823 0.234 ;
     RECT  10.427 2.07 10.975 15.21 ;
     RECT  10.903 1.152 11.003 1.17 ;
     RECT  10.939 16.65 11.255 16.668 ;
     RECT  10.975 2.07 11.435 15.246 ;
     RECT  10.823 0.036 11.471 0.162 ;
     RECT  11.551 17.118 11.587 17.136 ;
     RECT  11.587 17.118 11.687 17.208 ;
     RECT  11.435 2.106 11.767 15.246 ;
     RECT  12.271 1.152 12.739 1.17 ;
     RECT  12.739 1.152 12.839 1.242 ;
     RECT  11.767 2.106 13.091 15.399 ;
     RECT  12.839 1.152 14.423 1.17 ;
     RECT  13.091 2.151 14.467 15.399 ;
     RECT  15.187 1.152 15.287 1.17 ;
     RECT  15.223 17.118 15.323 17.208 ;
     RECT  15.323 17.19 15.359 17.208 ;
     RECT  14.467 2.106 15.547 15.399 ;
     RECT  15.547 2.034 16.123 15.399 ;
     RECT  11.471 0.144 16.411 0.162 ;
     RECT  16.123 1.422 16.411 15.399 ;
     RECT  16.375 17.118 16.411 17.136 ;
     RECT  16.411 17.118 16.511 17.208 ;
     RECT  16.411 0.144 17.411 15.399 ;
     RECT  17.411 0.846 18.571 15.399 ;
     RECT  18.571 0.144 20.651 15.399 ;
     RECT  20.651 0.846 21.199 15.399 ;
     RECT  21.199 0.846 21.523 15.516 ;
     RECT  21.523 0.036 21.659 15.516 ;
     RECT  21.659 0.036 23.76 15.399 ;
     RECT  23.76 3.816 23.783 10.854 ;
     RECT  23.76 2.304 23.963 2.628 ;
     RECT  23.783 3.816 24.107 8.604 ;
     RECT  23.76 0.036 24.323 1.44 ;
     RECT  23.783 9.522 24.323 10.854 ;
     RECT  24.107 3.816 24.511 5.22 ;
     RECT  24.323 0.036 24.539 0.126 ;
     RECT  23.76 11.682 24.575 15.399 ;
     RECT  24.575 14.796 24.611 15.399 ;
     RECT  24.107 5.976 24.647 8.604 ;
     RECT  24.575 11.682 24.683 13.968 ;
     RECT  24.647 5.976 24.719 6.804 ;
     RECT  24.683 11.682 24.719 11.7 ;
     RECT  24.323 1.152 24.755 1.44 ;
     RECT  24.683 13.068 24.755 13.968 ;
     RECT  24.539 0.036 24.791 0.09 ;
     RECT  24.511 3.42 24.827 5.22 ;
     RECT  24.791 0.072 24.863 0.09 ;
     RECT  24.755 1.152 24.863 1.242 ;
     RECT  24.647 7.938 24.899 8.604 ;
     RECT  24.323 9.864 24.971 10.854 ;
     RECT  24.827 4.464 24.979 5.22 ;
     RECT  24.719 5.976 24.979 6.714 ;
     RECT  24.863 1.152 25.007 1.17 ;
     RECT  24.979 4.464 25.115 6.714 ;
     RECT  24.899 7.938 25.115 7.956 ;
     RECT  24.971 10.296 25.115 10.854 ;
     RECT  25.115 5.076 25.151 6.714 ;
     RECT  24.611 14.796 25.151 15.048 ;
     RECT  25.151 5.076 25.187 6.408 ;
     RECT  25.115 10.296 25.187 10.809 ;
     RECT  25.187 5.076 25.223 6.066 ;
     RECT  24.755 13.446 25.223 13.968 ;
     RECT  25.223 5.076 25.259 5.724 ;
     RECT  23.963 2.61 25.295 2.628 ;
     RECT  25.151 15.03 25.295 15.048 ;
     RECT  25.259 5.076 25.331 5.094 ;
     RECT  25.187 10.296 25.331 10.314 ;
     RECT  25.223 13.95 25.367 13.968 ;
     RECT  24.827 3.42 25.403 3.438 ;
    LAYER M3 ;
     RECT  21.528 0.031 21.546 0.067 ;
     RECT  24.768 0.031 24.786 0.067 ;
     RECT  21.528 0.067 21.6 0.103 ;
     RECT  21.618 0.067 21.744 0.103 ;
     RECT  21.762 0.067 21.924 0.103 ;
     RECT  21.942 0.067 22.068 0.103 ;
     RECT  22.086 0.067 22.194 0.103 ;
     RECT  24.768 0.067 24.858 0.103 ;
     RECT  7.956 0.031 7.974 0.108 ;
     RECT  11.448 0.031 11.466 0.108 ;
     RECT  21.528 0.103 21.6 0.108 ;
     RECT  21.618 0.103 21.744 0.108 ;
     RECT  21.762 0.103 21.924 0.108 ;
     RECT  21.942 0.103 22.068 0.108 ;
     RECT  22.086 0.103 22.212 0.108 ;
     RECT  22.23 0.103 22.392 0.108 ;
     RECT  22.41 0.103 22.482 0.108 ;
     RECT  2.214 0.108 2.34 0.139 ;
     RECT  2.358 0.108 2.52 0.139 ;
     RECT  2.538 0.108 2.664 0.139 ;
     RECT  2.682 0.108 2.808 0.139 ;
     RECT  2.826 0.108 2.988 0.139 ;
     RECT  3.006 0.108 3.132 0.139 ;
     RECT  3.15 0.108 3.276 0.139 ;
     RECT  3.294 0.108 3.456 0.139 ;
     RECT  3.474 0.108 3.6 0.139 ;
     RECT  3.618 0.108 3.744 0.139 ;
     RECT  3.762 0.108 3.924 0.139 ;
     RECT  3.942 0.108 4.068 0.139 ;
     RECT  4.086 0.108 4.212 0.139 ;
     RECT  4.23 0.108 4.392 0.139 ;
     RECT  4.41 0.108 4.536 0.139 ;
     RECT  4.554 0.108 4.68 0.139 ;
     RECT  4.698 0.108 4.86 0.139 ;
     RECT  4.878 0.108 5.004 0.139 ;
     RECT  5.022 0.108 5.148 0.139 ;
     RECT  5.166 0.108 5.328 0.139 ;
     RECT  5.346 0.108 5.472 0.139 ;
     RECT  5.49 0.108 5.616 0.139 ;
     RECT  5.634 0.108 5.796 0.139 ;
     RECT  5.814 0.108 5.94 0.139 ;
     RECT  5.958 0.108 6.12 0.139 ;
     RECT  6.138 0.108 6.264 0.139 ;
     RECT  6.282 0.108 6.408 0.139 ;
     RECT  6.426 0.108 6.588 0.139 ;
     RECT  6.606 0.108 6.732 0.139 ;
     RECT  6.75 0.108 6.876 0.139 ;
     RECT  6.894 0.108 7.056 0.139 ;
     RECT  7.074 0.108 7.2 0.139 ;
     RECT  7.218 0.108 7.344 0.139 ;
     RECT  7.362 0.108 7.524 0.139 ;
     RECT  7.542 0.108 7.668 0.139 ;
     RECT  7.686 0.108 7.812 0.139 ;
     RECT  7.83 0.108 7.992 0.139 ;
     RECT  8.01 0.108 8.136 0.139 ;
     RECT  8.154 0.108 8.28 0.139 ;
     RECT  8.298 0.108 8.46 0.139 ;
     RECT  8.478 0.108 8.604 0.139 ;
     RECT  8.622 0.108 8.748 0.139 ;
     RECT  8.766 0.108 8.928 0.139 ;
     RECT  8.946 0.108 9.072 0.139 ;
     RECT  9.09 0.108 9.216 0.139 ;
     RECT  9.234 0.108 9.396 0.139 ;
     RECT  9.414 0.108 9.54 0.139 ;
     RECT  9.558 0.108 9.72 0.139 ;
     RECT  9.738 0.108 9.864 0.139 ;
     RECT  9.882 0.108 10.008 0.139 ;
     RECT  10.026 0.108 10.188 0.139 ;
     RECT  10.206 0.108 10.332 0.139 ;
     RECT  10.35 0.108 10.476 0.139 ;
     RECT  10.494 0.108 10.656 0.139 ;
     RECT  10.674 0.108 10.8 0.139 ;
     RECT  10.818 0.108 10.944 0.139 ;
     RECT  10.962 0.108 11.124 0.139 ;
     RECT  11.142 0.108 11.268 0.139 ;
     RECT  11.286 0.108 11.412 0.139 ;
     RECT  11.43 0.108 11.592 0.139 ;
     RECT  11.61 0.108 11.736 0.139 ;
     RECT  11.754 0.108 11.88 0.139 ;
     RECT  11.898 0.108 12.06 0.139 ;
     RECT  12.078 0.108 12.204 0.139 ;
     RECT  12.222 0.108 12.348 0.139 ;
     RECT  12.366 0.108 12.528 0.139 ;
     RECT  12.546 0.108 12.672 0.139 ;
     RECT  12.69 0.108 12.816 0.139 ;
     RECT  12.834 0.108 12.996 0.139 ;
     RECT  13.014 0.108 13.14 0.139 ;
     RECT  13.158 0.108 13.32 0.139 ;
     RECT  13.338 0.108 13.464 0.139 ;
     RECT  13.482 0.108 13.608 0.139 ;
     RECT  13.626 0.108 13.788 0.139 ;
     RECT  13.806 0.108 13.932 0.139 ;
     RECT  13.95 0.108 14.076 0.139 ;
     RECT  14.094 0.108 14.256 0.139 ;
     RECT  14.274 0.108 14.4 0.139 ;
     RECT  14.418 0.108 14.544 0.139 ;
     RECT  14.562 0.108 14.724 0.139 ;
     RECT  14.742 0.108 14.868 0.139 ;
     RECT  14.886 0.108 15.012 0.139 ;
     RECT  15.03 0.108 15.192 0.139 ;
     RECT  15.21 0.108 15.336 0.139 ;
     RECT  15.354 0.108 15.48 0.139 ;
     RECT  15.498 0.108 15.66 0.139 ;
     RECT  15.678 0.108 15.804 0.139 ;
     RECT  15.822 0.108 15.948 0.139 ;
     RECT  15.966 0.108 16.128 0.139 ;
     RECT  16.146 0.108 16.272 0.139 ;
     RECT  16.29 0.108 16.416 0.139 ;
     RECT  16.434 0.108 16.596 0.139 ;
     RECT  16.614 0.108 16.74 0.139 ;
     RECT  16.758 0.108 16.92 0.139 ;
     RECT  16.938 0.108 17.064 0.139 ;
     RECT  17.082 0.108 17.208 0.139 ;
     RECT  17.226 0.108 17.388 0.139 ;
     RECT  17.406 0.108 17.532 0.139 ;
     RECT  17.55 0.108 17.676 0.139 ;
     RECT  17.694 0.108 17.856 0.139 ;
     RECT  17.874 0.108 18 0.139 ;
     RECT  18.018 0.108 18.144 0.139 ;
     RECT  18.162 0.108 18.324 0.139 ;
     RECT  18.342 0.108 18.468 0.139 ;
     RECT  18.486 0.108 18.612 0.139 ;
     RECT  18.63 0.108 18.792 0.139 ;
     RECT  18.81 0.108 18.936 0.139 ;
     RECT  18.954 0.108 19.08 0.139 ;
     RECT  19.098 0.108 19.26 0.139 ;
     RECT  19.278 0.108 19.404 0.139 ;
     RECT  19.422 0.108 19.548 0.139 ;
     RECT  19.566 0.108 19.728 0.139 ;
     RECT  19.746 0.108 19.872 0.139 ;
     RECT  19.89 0.108 20.016 0.139 ;
     RECT  20.034 0.108 20.196 0.139 ;
     RECT  20.214 0.108 20.34 0.139 ;
     RECT  20.358 0.108 20.52 0.139 ;
     RECT  20.538 0.108 20.664 0.139 ;
     RECT  20.682 0.108 20.808 0.139 ;
     RECT  20.826 0.108 20.988 0.139 ;
     RECT  21.006 0.108 21.132 0.139 ;
     RECT  21.15 0.108 21.276 0.139 ;
     RECT  21.294 0.108 21.456 0.139 ;
     RECT  21.474 0.108 21.6 0.139 ;
     RECT  21.618 0.108 21.744 0.139 ;
     RECT  21.762 0.108 21.924 0.139 ;
     RECT  21.942 0.108 22.068 0.139 ;
     RECT  22.086 0.108 22.212 0.139 ;
     RECT  22.23 0.108 22.392 0.139 ;
     RECT  22.41 0.108 22.536 0.139 ;
     RECT  22.554 0.108 22.68 0.139 ;
     RECT  22.698 0.108 22.86 0.139 ;
     RECT  22.878 0.108 23.004 0.139 ;
     RECT  23.022 0.108 23.148 0.139 ;
     RECT  23.166 0.108 23.328 0.139 ;
     RECT  23.346 0.108 23.472 0.139 ;
     RECT  23.49 0.108 23.616 0.139 ;
     RECT  24.516 0.103 24.858 0.139 ;
     RECT  2.124 0.139 2.196 0.144 ;
     RECT  2.214 0.139 2.34 0.144 ;
     RECT  2.358 0.139 2.52 0.144 ;
     RECT  2.538 0.139 2.664 0.144 ;
     RECT  2.682 0.139 2.808 0.144 ;
     RECT  2.826 0.139 2.988 0.144 ;
     RECT  3.006 0.139 3.132 0.144 ;
     RECT  3.15 0.139 3.276 0.144 ;
     RECT  3.294 0.139 3.456 0.144 ;
     RECT  3.474 0.139 3.6 0.144 ;
     RECT  3.618 0.139 3.744 0.144 ;
     RECT  3.762 0.139 3.924 0.144 ;
     RECT  3.942 0.139 4.068 0.144 ;
     RECT  4.086 0.139 4.212 0.144 ;
     RECT  4.23 0.139 4.392 0.144 ;
     RECT  4.41 0.139 4.536 0.144 ;
     RECT  4.554 0.139 4.68 0.144 ;
     RECT  4.698 0.139 4.86 0.144 ;
     RECT  4.878 0.139 5.004 0.144 ;
     RECT  5.022 0.139 5.148 0.144 ;
     RECT  5.166 0.139 5.328 0.144 ;
     RECT  5.346 0.139 5.472 0.144 ;
     RECT  5.49 0.139 5.616 0.144 ;
     RECT  5.634 0.139 5.796 0.144 ;
     RECT  5.814 0.139 5.94 0.144 ;
     RECT  5.958 0.139 6.12 0.144 ;
     RECT  6.138 0.139 6.264 0.144 ;
     RECT  6.282 0.139 6.408 0.144 ;
     RECT  6.426 0.139 6.588 0.144 ;
     RECT  6.606 0.139 6.732 0.144 ;
     RECT  6.75 0.139 6.876 0.144 ;
     RECT  6.894 0.139 7.056 0.144 ;
     RECT  7.074 0.139 7.2 0.144 ;
     RECT  7.218 0.139 7.344 0.144 ;
     RECT  7.362 0.139 7.524 0.144 ;
     RECT  7.542 0.139 7.668 0.144 ;
     RECT  7.686 0.139 7.812 0.144 ;
     RECT  7.83 0.139 7.992 0.144 ;
     RECT  8.01 0.139 8.136 0.144 ;
     RECT  8.154 0.139 8.28 0.144 ;
     RECT  8.298 0.139 8.46 0.144 ;
     RECT  8.478 0.139 8.604 0.144 ;
     RECT  8.622 0.139 8.748 0.144 ;
     RECT  8.766 0.139 8.928 0.144 ;
     RECT  8.946 0.139 9.072 0.144 ;
     RECT  9.09 0.139 9.216 0.144 ;
     RECT  9.234 0.139 9.396 0.144 ;
     RECT  9.414 0.139 9.54 0.144 ;
     RECT  9.558 0.139 9.72 0.144 ;
     RECT  9.738 0.139 9.864 0.144 ;
     RECT  9.882 0.139 10.008 0.144 ;
     RECT  10.026 0.139 10.188 0.144 ;
     RECT  10.206 0.139 10.332 0.144 ;
     RECT  10.35 0.139 10.476 0.144 ;
     RECT  10.494 0.139 10.656 0.144 ;
     RECT  10.674 0.139 10.8 0.144 ;
     RECT  10.818 0.139 10.944 0.144 ;
     RECT  10.962 0.139 11.124 0.144 ;
     RECT  11.142 0.139 11.268 0.144 ;
     RECT  11.286 0.139 11.412 0.144 ;
     RECT  11.43 0.139 11.592 0.144 ;
     RECT  11.61 0.139 11.736 0.144 ;
     RECT  11.754 0.139 11.88 0.144 ;
     RECT  11.898 0.139 12.06 0.144 ;
     RECT  12.078 0.139 12.204 0.144 ;
     RECT  12.222 0.139 12.348 0.144 ;
     RECT  12.366 0.139 12.528 0.144 ;
     RECT  12.546 0.139 12.672 0.144 ;
     RECT  12.69 0.139 12.816 0.144 ;
     RECT  12.834 0.139 12.996 0.144 ;
     RECT  13.014 0.139 13.14 0.144 ;
     RECT  13.158 0.139 13.32 0.144 ;
     RECT  13.338 0.139 13.464 0.144 ;
     RECT  13.482 0.139 13.608 0.144 ;
     RECT  13.626 0.139 13.788 0.144 ;
     RECT  13.806 0.139 13.932 0.144 ;
     RECT  13.95 0.139 14.076 0.144 ;
     RECT  14.094 0.139 14.256 0.144 ;
     RECT  14.274 0.139 14.4 0.144 ;
     RECT  14.418 0.139 14.544 0.144 ;
     RECT  14.562 0.139 14.724 0.144 ;
     RECT  14.742 0.139 14.868 0.144 ;
     RECT  14.886 0.139 15.012 0.144 ;
     RECT  15.03 0.139 15.192 0.144 ;
     RECT  15.21 0.139 15.336 0.144 ;
     RECT  15.354 0.139 15.48 0.144 ;
     RECT  15.498 0.139 15.66 0.144 ;
     RECT  15.678 0.139 15.804 0.144 ;
     RECT  15.822 0.139 15.948 0.144 ;
     RECT  15.966 0.139 16.128 0.144 ;
     RECT  16.146 0.139 16.272 0.144 ;
     RECT  16.29 0.139 16.416 0.144 ;
     RECT  16.434 0.139 16.596 0.144 ;
     RECT  16.614 0.139 16.74 0.144 ;
     RECT  16.758 0.139 16.92 0.144 ;
     RECT  16.938 0.139 17.064 0.144 ;
     RECT  17.082 0.139 17.208 0.144 ;
     RECT  17.226 0.139 17.388 0.144 ;
     RECT  17.406 0.139 17.532 0.144 ;
     RECT  17.55 0.139 17.676 0.144 ;
     RECT  17.694 0.139 17.856 0.144 ;
     RECT  17.874 0.139 18 0.144 ;
     RECT  18.018 0.139 18.144 0.144 ;
     RECT  18.162 0.139 18.324 0.144 ;
     RECT  18.342 0.139 18.468 0.144 ;
     RECT  18.486 0.139 18.612 0.144 ;
     RECT  18.63 0.139 18.792 0.144 ;
     RECT  18.81 0.139 18.936 0.144 ;
     RECT  18.954 0.139 19.08 0.144 ;
     RECT  19.098 0.139 19.26 0.144 ;
     RECT  19.278 0.139 19.404 0.144 ;
     RECT  19.422 0.139 19.548 0.144 ;
     RECT  19.566 0.139 19.728 0.144 ;
     RECT  19.746 0.139 19.872 0.144 ;
     RECT  19.89 0.139 20.016 0.144 ;
     RECT  20.034 0.139 20.196 0.144 ;
     RECT  20.214 0.139 20.34 0.144 ;
     RECT  20.358 0.139 20.52 0.144 ;
     RECT  20.538 0.139 20.664 0.144 ;
     RECT  20.682 0.139 20.808 0.144 ;
     RECT  20.826 0.139 20.988 0.144 ;
     RECT  21.006 0.139 21.132 0.144 ;
     RECT  21.15 0.139 21.276 0.144 ;
     RECT  21.294 0.139 21.456 0.144 ;
     RECT  21.474 0.139 21.6 0.144 ;
     RECT  21.618 0.139 21.744 0.144 ;
     RECT  21.762 0.139 21.924 0.144 ;
     RECT  21.942 0.139 22.068 0.144 ;
     RECT  22.086 0.139 22.212 0.144 ;
     RECT  22.23 0.139 22.392 0.144 ;
     RECT  22.41 0.139 22.536 0.144 ;
     RECT  22.554 0.139 22.68 0.144 ;
     RECT  22.698 0.139 22.86 0.144 ;
     RECT  22.878 0.139 23.004 0.144 ;
     RECT  23.022 0.139 23.148 0.144 ;
     RECT  23.166 0.139 23.328 0.144 ;
     RECT  23.346 0.139 23.472 0.144 ;
     RECT  23.49 0.139 23.616 0.144 ;
     RECT  23.634 0.139 24.858 0.144 ;
     RECT  2.124 0.144 24.858 0.317 ;
     RECT  0.792 0.235 0.81 0.379 ;
     RECT  0.792 0.379 1.386 0.841 ;
     RECT  2.124 0.317 22.446 0.841 ;
     RECT  0.792 0.841 22.446 0.859 ;
     RECT  23.724 0.317 24.858 1.147 ;
     RECT  0.468 0.859 22.446 2.101 ;
     RECT  23.256 1.147 25.002 2.101 ;
     RECT  0.468 2.101 25.002 2.605 ;
     RECT  0.468 2.605 25.29 2.827 ;
     RECT  0.36 2.827 25.29 3.415 ;
     RECT  0.36 3.415 25.398 3.979 ;
     RECT  0.288 3.979 25.398 7.181 ;
     RECT  0.288 7.181 25.362 11.507 ;
     RECT  1.08 11.507 25.362 11.939 ;
     RECT  1.08 11.939 1.242 12.317 ;
     RECT  1.98 11.939 25.362 12.623 ;
     RECT  1.116 12.317 1.242 13.099 ;
     RECT  1.116 13.099 1.314 13.397 ;
     RECT  1.152 13.397 1.314 13.433 ;
     RECT  0.288 11.507 0.306 13.469 ;
     RECT  1.152 13.433 1.242 13.661 ;
     RECT  2.196 12.623 25.362 13.973 ;
     RECT  1.224 13.661 1.242 14.279 ;
     RECT  2.196 13.973 25.29 14.477 ;
     RECT  24.516 14.477 25.29 14.783 ;
     RECT  24.588 14.783 25.29 15.053 ;
     RECT  2.196 14.477 23.562 15.331 ;
     RECT  24.588 15.053 24.606 15.404 ;
     RECT  2.196 15.331 23.742 17.136 ;
     RECT  2.214 17.136 2.34 17.148 ;
     RECT  2.358 17.136 2.484 17.148 ;
     RECT  2.502 17.136 2.664 17.148 ;
     RECT  2.682 17.136 2.808 17.148 ;
     RECT  2.826 17.136 2.952 17.148 ;
     RECT  2.97 17.136 3.132 17.148 ;
     RECT  3.15 17.136 3.276 17.148 ;
     RECT  3.294 17.136 3.42 17.148 ;
     RECT  3.438 17.136 3.6 17.148 ;
     RECT  3.618 17.136 3.744 17.148 ;
     RECT  3.762 17.136 3.888 17.148 ;
     RECT  3.906 17.136 4.068 17.148 ;
     RECT  4.086 17.136 4.212 17.148 ;
     RECT  4.23 17.136 4.356 17.148 ;
     RECT  4.374 17.136 4.536 17.148 ;
     RECT  4.554 17.136 4.68 17.148 ;
     RECT  4.698 17.136 4.824 17.148 ;
     RECT  4.842 17.136 5.004 17.148 ;
     RECT  5.022 17.136 5.148 17.148 ;
     RECT  5.166 17.136 5.292 17.148 ;
     RECT  5.31 17.136 5.472 17.148 ;
     RECT  5.49 17.136 5.616 17.148 ;
     RECT  5.634 17.136 5.76 17.148 ;
     RECT  5.778 17.136 5.94 17.148 ;
     RECT  5.958 17.136 6.084 17.148 ;
     RECT  6.102 17.136 6.228 17.148 ;
     RECT  6.246 17.136 6.408 17.148 ;
     RECT  6.426 17.136 6.552 17.148 ;
     RECT  6.57 17.136 6.696 17.148 ;
     RECT  6.714 17.136 6.876 17.148 ;
     RECT  6.894 17.136 7.02 17.148 ;
     RECT  7.038 17.136 7.164 17.148 ;
     RECT  7.182 17.136 7.344 17.148 ;
     RECT  7.362 17.136 7.488 17.148 ;
     RECT  7.506 17.136 7.632 17.148 ;
     RECT  7.65 17.136 7.812 17.148 ;
     RECT  7.83 17.136 7.956 17.148 ;
     RECT  7.974 17.136 8.1 17.148 ;
     RECT  8.118 17.136 8.28 17.148 ;
     RECT  8.298 17.136 8.424 17.148 ;
     RECT  8.442 17.136 8.568 17.148 ;
     RECT  8.586 17.136 8.748 17.148 ;
     RECT  8.766 17.136 8.892 17.148 ;
     RECT  8.91 17.136 9.036 17.148 ;
     RECT  9.054 17.136 9.216 17.148 ;
     RECT  9.234 17.136 9.36 17.148 ;
     RECT  9.378 17.136 9.504 17.148 ;
     RECT  9.522 17.136 9.684 17.148 ;
     RECT  9.702 17.136 9.828 17.148 ;
     RECT  9.846 17.136 9.972 17.148 ;
     RECT  9.99 17.136 10.152 17.148 ;
     RECT  10.17 17.136 10.296 17.148 ;
     RECT  10.314 17.136 10.44 17.148 ;
     RECT  10.458 17.136 10.62 17.148 ;
     RECT  10.638 17.136 10.764 17.148 ;
     RECT  10.782 17.136 10.908 17.148 ;
     RECT  10.926 17.136 11.088 17.148 ;
     RECT  11.106 17.136 11.232 17.148 ;
     RECT  11.25 17.136 11.376 17.148 ;
     RECT  11.394 17.136 11.556 17.148 ;
     RECT  11.574 17.136 11.7 17.148 ;
     RECT  11.718 17.136 11.844 17.148 ;
     RECT  11.862 17.136 12.024 17.148 ;
     RECT  12.042 17.136 12.168 17.148 ;
     RECT  12.186 17.136 12.312 17.148 ;
     RECT  12.33 17.136 12.492 17.148 ;
     RECT  12.51 17.136 12.636 17.148 ;
     RECT  12.654 17.136 12.78 17.148 ;
     RECT  12.798 17.136 12.96 17.148 ;
     RECT  12.978 17.136 13.104 17.148 ;
     RECT  13.122 17.136 13.248 17.148 ;
     RECT  13.266 17.136 13.428 17.148 ;
     RECT  13.446 17.136 13.572 17.148 ;
     RECT  13.59 17.136 13.716 17.148 ;
     RECT  13.734 17.136 13.896 17.148 ;
     RECT  13.914 17.136 14.04 17.148 ;
     RECT  14.058 17.136 14.184 17.148 ;
     RECT  14.202 17.136 14.364 17.148 ;
     RECT  14.382 17.136 14.508 17.148 ;
     RECT  14.526 17.136 14.652 17.148 ;
     RECT  14.67 17.136 14.832 17.148 ;
     RECT  14.85 17.136 14.976 17.148 ;
     RECT  14.994 17.136 15.12 17.148 ;
     RECT  15.138 17.136 15.3 17.148 ;
     RECT  15.318 17.136 15.444 17.148 ;
     RECT  15.462 17.136 15.588 17.148 ;
     RECT  15.606 17.136 15.768 17.148 ;
     RECT  15.786 17.136 15.912 17.148 ;
     RECT  15.93 17.136 16.056 17.148 ;
     RECT  16.074 17.136 16.236 17.148 ;
     RECT  16.254 17.136 16.38 17.148 ;
     RECT  16.398 17.136 16.524 17.148 ;
     RECT  16.542 17.136 16.704 17.148 ;
     RECT  16.722 17.136 16.848 17.148 ;
     RECT  16.866 17.136 16.992 17.148 ;
     RECT  17.01 17.136 17.172 17.148 ;
     RECT  17.19 17.136 17.316 17.148 ;
     RECT  17.334 17.136 17.46 17.148 ;
     RECT  17.478 17.136 17.64 17.148 ;
     RECT  17.658 17.136 17.784 17.148 ;
     RECT  17.802 17.136 17.928 17.148 ;
     RECT  17.946 17.136 18.108 17.148 ;
     RECT  18.126 17.136 18.252 17.148 ;
     RECT  18.27 17.136 18.396 17.148 ;
     RECT  18.414 17.136 18.576 17.148 ;
     RECT  18.594 17.136 18.72 17.148 ;
     RECT  18.738 17.136 18.864 17.148 ;
     RECT  18.882 17.136 19.044 17.148 ;
     RECT  19.062 17.136 19.188 17.148 ;
     RECT  19.206 17.136 19.332 17.148 ;
     RECT  19.35 17.136 19.512 17.148 ;
     RECT  19.53 17.136 19.656 17.148 ;
     RECT  19.674 17.136 19.8 17.148 ;
     RECT  19.818 17.136 19.98 17.148 ;
     RECT  19.998 17.136 20.124 17.148 ;
     RECT  20.142 17.136 20.268 17.148 ;
     RECT  20.286 17.136 20.448 17.148 ;
     RECT  20.466 17.136 20.592 17.148 ;
     RECT  20.61 17.136 20.736 17.148 ;
     RECT  20.754 17.136 20.916 17.148 ;
     RECT  20.934 17.136 21.06 17.148 ;
     RECT  21.078 17.136 21.204 17.148 ;
     RECT  21.222 17.136 21.384 17.148 ;
     RECT  21.402 17.136 21.528 17.148 ;
     RECT  21.546 17.136 21.672 17.148 ;
     RECT  21.69 17.136 21.852 17.148 ;
     RECT  21.87 17.136 21.996 17.148 ;
     RECT  22.014 17.136 22.14 17.148 ;
     RECT  22.158 17.136 22.32 17.148 ;
     RECT  22.338 17.136 22.464 17.148 ;
     RECT  22.482 17.136 22.608 17.148 ;
     RECT  22.626 17.136 22.788 17.148 ;
     RECT  22.806 17.136 22.932 17.148 ;
     RECT  22.95 17.136 23.076 17.148 ;
     RECT  23.094 17.136 23.256 17.148 ;
     RECT  23.274 17.136 23.4 17.148 ;
     RECT  23.418 17.136 23.544 17.148 ;
     RECT  23.562 17.136 23.724 17.148 ;
     RECT  11.592 17.148 11.682 17.213 ;
     RECT  16.416 17.148 16.506 17.213 ;
    LAYER M4 ;
     RECT  0.277 3.984 0.325 4.008 ;
     RECT  0.277 2.784 0.349 2.808 ;
     RECT  0.325 3.936 0.373 4.008 ;
     RECT  0.349 2.784 0.421 2.856 ;
     RECT  0.373 3.936 0.421 4.2 ;
     RECT  0.325 12.048 0.421 12.072 ;
     RECT  0.373 13.392 0.469 13.416 ;
     RECT  0.457 0.864 0.709 0.888 ;
     RECT  0.421 1.92 0.709 4.2 ;
     RECT  0.469 13.344 0.709 13.416 ;
     RECT  0.709 6.912 0.757 6.936 ;
     RECT  0.709 0.864 0.781 4.2 ;
     RECT  0.757 6.624 0.853 6.936 ;
     RECT  0.781 0.24 0.901 4.2 ;
     RECT  0.853 6.624 0.901 7.464 ;
     RECT  0.805 8.448 0.901 8.472 ;
     RECT  0.901 6.624 0.949 8.472 ;
     RECT  0.961 5.568 0.997 5.592 ;
     RECT  0.949 6.624 0.997 8.856 ;
     RECT  0.421 12 0.997 12.072 ;
     RECT  0.709 13.104 0.997 13.416 ;
     RECT  0.277 14.928 1.045 14.952 ;
     RECT  0.901 0.24 1.069 4.536 ;
     RECT  0.997 5.568 1.069 8.856 ;
     RECT  0.997 12 1.141 13.416 ;
     RECT  1.045 14.448 1.141 14.952 ;
     RECT  1.069 0.24 1.381 8.856 ;
     RECT  1.141 12 1.621 14.952 ;
     RECT  1.621 11.712 1.669 14.952 ;
     RECT  1.429 10.608 2.101 10.632 ;
     RECT  2.101 10.272 2.293 10.632 ;
     RECT  1.669 11.712 2.293 15 ;
     RECT  1.381 0.144 2.408 8.856 ;
     RECT  2.293 10.272 2.408 15.288 ;
     RECT  2.408 0.144 2.54 15.288 ;
     RECT  2.54 0.144 2.627 16.008 ;
     RECT  2.627 0.144 2.812 15.24 ;
     RECT  2.812 0.144 2.845 15.144 ;
     RECT  2.845 0.144 3.973 15.096 ;
     RECT  3.973 0.144 4.22 15.432 ;
     RECT  4.22 0.144 4.307 16.008 ;
     RECT  4.307 0.144 4.684 15.432 ;
     RECT  4.684 0.144 5.404 15.288 ;
     RECT  5.404 10.608 5.651 15.288 ;
     RECT  7.093 16.56 7.229 16.584 ;
     RECT  5.404 0.144 7.244 8.856 ;
     RECT  7.244 0.144 7.477 9.096 ;
     RECT  5.651 10.608 7.477 15.048 ;
     RECT  7.477 0.144 7.525 15.048 ;
     RECT  7.649 16.992 7.693 17.016 ;
     RECT  7.693 16.992 7.733 17.112 ;
     RECT  7.525 0.144 7.762 15.24 ;
     RECT  7.762 0.144 8.005 15.288 ;
     RECT  8.005 0.144 8.104 16.008 ;
     RECT  8.104 0.144 8.165 13.656 ;
     RECT  8.104 14.832 8.453 16.008 ;
     RECT  8.165 0.144 8.705 12.024 ;
     RECT  8.165 13.104 9.389 13.656 ;
     RECT  8.705 10.608 9.637 12.024 ;
     RECT  9.389 13.632 9.853 13.656 ;
     RECT  8.453 14.832 9.853 15.096 ;
     RECT  9.853 13.632 10.028 15.096 ;
     RECT  8.705 0.144 10.213 9 ;
     RECT  9.637 10.608 10.261 12.552 ;
     RECT  10.028 13.632 10.357 15.432 ;
     RECT  10.261 10.32 10.393 12.552 ;
     RECT  10.357 13.632 10.393 16.008 ;
     RECT  10.213 0.144 10.508 9.24 ;
     RECT  10.393 10.32 10.508 16.008 ;
     RECT  10.508 0.144 10.804 16.008 ;
     RECT  10.804 10.32 10.865 13.752 ;
     RECT  10.804 14.832 11.125 16.008 ;
     RECT  7.733 17.088 11.125 17.112 ;
     RECT  10.804 0.144 11.153 9.144 ;
     RECT  11.153 0.144 11.171 1.176 ;
     RECT  10.865 10.608 11.267 13.752 ;
     RECT  11.153 2.256 11.333 9.144 ;
     RECT  11.267 13.632 11.405 13.752 ;
     RECT  11.171 0.144 11.441 0.84 ;
     RECT  11.441 0.144 11.699 0.552 ;
     RECT  11.333 2.352 11.833 9.144 ;
     RECT  11.125 14.832 11.837 17.112 ;
     RECT  11.837 14.832 11.909 16.008 ;
     RECT  11.909 14.832 11.981 15.096 ;
     RECT  11.405 13.68 12.085 13.752 ;
     RECT  11.981 14.832 12.085 14.904 ;
     RECT  11.699 0.144 12.233 0.408 ;
     RECT  11.833 2.352 12.625 9.192 ;
     RECT  12.625 2.352 12.689 9.528 ;
     RECT  11.267 10.608 12.689 12.552 ;
     RECT  12.233 0.288 12.757 0.408 ;
     RECT  12.689 2.352 12.949 12.552 ;
     RECT  12.085 13.68 12.956 14.904 ;
     RECT  11.837 17.088 12.989 17.112 ;
     RECT  12.956 13.68 13.189 15.432 ;
     RECT  12.949 2.256 13.208 12.552 ;
     RECT  13.189 13.68 13.208 16.008 ;
     RECT  13.208 2.148 13.312 16.008 ;
     RECT  13.312 2.256 13.504 16.008 ;
     RECT  12.757 0.288 13.619 1.176 ;
     RECT  13.504 2.256 13.715 11.976 ;
     RECT  13.715 2.352 13.853 11.976 ;
     RECT  13.504 14.736 13.955 16.008 ;
     RECT  13.955 14.832 14.249 16.008 ;
     RECT  13.504 13.104 14.789 13.128 ;
     RECT  13.853 2.496 14.869 11.976 ;
     RECT  13.619 0.288 14.917 0.408 ;
     RECT  14.917 0.192 14.965 0.408 ;
     RECT  14.249 14.832 15.037 15 ;
     RECT  14.965 0.192 15.155 1.176 ;
     RECT  14.869 2.496 15.469 13.08 ;
     RECT  15.037 14.496 15.577 15 ;
     RECT  15.469 2.352 15.637 13.08 ;
     RECT  14.249 15.984 15.875 16.008 ;
     RECT  15.637 1.728 15.908 13.08 ;
     RECT  15.577 14.112 15.908 15 ;
     RECT  15.155 0.192 16.165 0.408 ;
     RECT  16.165 0.192 16.213 0.456 ;
     RECT  15.908 1.728 16.213 15.432 ;
     RECT  16.117 16.56 16.301 16.584 ;
     RECT  16.213 0.192 17.075 15.432 ;
     RECT  16.981 16.992 17.123 17.016 ;
     RECT  17.075 1.968 17.221 15.432 ;
     RECT  17.221 1.968 17.557 16.008 ;
     RECT  17.075 0.192 18.035 0.552 ;
     RECT  18.035 0.288 18.373 0.552 ;
     RECT  18.373 0.288 18.563 0.936 ;
     RECT  17.557 1.968 19.249 16.056 ;
     RECT  18.563 0.288 19.717 0.84 ;
     RECT  19.249 1.968 19.717 16.584 ;
     RECT  19.717 0.288 20.197 16.584 ;
     RECT  20.197 0.288 20.369 16.632 ;
     RECT  20.369 0.288 20.867 16.584 ;
     RECT  20.867 0.288 22.213 16.056 ;
     RECT  22.213 0.144 23.101 16.056 ;
     RECT  23.101 0.144 23.363 16.584 ;
     RECT  23.363 0.144 23.651 15.672 ;
     RECT  23.651 0.144 23.861 15.048 ;
     RECT  23.861 0.144 24.035 6.168 ;
     RECT  23.861 7.152 24.179 15.048 ;
     RECT  24.035 0.144 24.221 5.16 ;
     RECT  24.221 0.816 24.437 5.16 ;
     RECT  24.179 7.152 24.611 14.76 ;
     RECT  24.611 7.152 24.617 10.104 ;
     RECT  24.611 11.184 24.707 14.76 ;
     RECT  24.437 2.496 24.755 5.16 ;
     RECT  24.437 0.816 24.761 0.84 ;
     RECT  24.617 7.152 24.761 9.912 ;
     RECT  24.707 11.184 24.803 14.664 ;
     RECT  24.755 2.496 24.851 3.336 ;
     RECT  24.803 11.904 24.851 14.664 ;
     RECT  24.851 2.496 24.899 3.096 ;
     RECT  24.851 14.64 24.899 14.664 ;
     RECT  24.755 4.656 24.905 5.16 ;
     RECT  24.761 8.208 24.941 9.912 ;
     RECT  24.899 2.496 24.947 2.904 ;
     RECT  24.851 11.904 24.947 12.84 ;
     RECT  24.947 2.88 24.977 2.904 ;
     RECT  24.905 5.136 24.995 5.16 ;
     RECT  24.941 8.208 24.995 9.624 ;
     RECT  24.995 8.736 25.265 9.624 ;
     RECT  24.035 6.144 25.373 6.168 ;
     RECT  24.761 7.152 25.409 7.176 ;
     RECT  25.74 5.664 25.763 5.688 ;
     RECT  25.265 8.736 25.763 8.76 ;
    LAYER M5 ;
     RECT  1.392 0.133 1.416 0.144 ;
     RECT  22.224 0.133 22.248 0.144 ;
     RECT  1.392 0.144 2.256 0.181 ;
     RECT  2.28 0.144 2.4 0.181 ;
     RECT  2.424 0.144 2.592 0.181 ;
     RECT  2.616 0.144 2.736 0.181 ;
     RECT  2.76 0.144 2.88 0.181 ;
     RECT  2.904 0.144 3.072 0.181 ;
     RECT  3.096 0.144 3.216 0.181 ;
     RECT  3.24 0.144 3.36 0.181 ;
     RECT  3.384 0.144 3.504 0.181 ;
     RECT  3.528 0.144 3.696 0.181 ;
     RECT  3.72 0.144 3.84 0.181 ;
     RECT  3.864 0.144 3.984 0.181 ;
     RECT  4.008 0.144 4.128 0.181 ;
     RECT  4.152 0.144 4.32 0.181 ;
     RECT  4.344 0.144 4.464 0.181 ;
     RECT  4.488 0.144 4.608 0.181 ;
     RECT  4.632 0.144 4.752 0.181 ;
     RECT  4.776 0.144 4.944 0.181 ;
     RECT  4.968 0.144 5.088 0.181 ;
     RECT  5.112 0.144 5.232 0.181 ;
     RECT  5.256 0.144 5.376 0.181 ;
     RECT  5.4 0.144 5.568 0.181 ;
     RECT  5.592 0.144 5.712 0.181 ;
     RECT  5.736 0.144 5.856 0.181 ;
     RECT  5.88 0.144 6 0.181 ;
     RECT  6.024 0.144 6.192 0.181 ;
     RECT  6.216 0.144 6.336 0.181 ;
     RECT  6.36 0.144 6.48 0.181 ;
     RECT  6.504 0.144 6.624 0.181 ;
     RECT  6.648 0.144 6.816 0.181 ;
     RECT  6.84 0.144 6.96 0.181 ;
     RECT  6.984 0.144 7.104 0.181 ;
     RECT  7.128 0.144 7.296 0.181 ;
     RECT  7.32 0.144 7.44 0.181 ;
     RECT  7.464 0.144 7.584 0.181 ;
     RECT  7.608 0.144 7.728 0.181 ;
     RECT  7.752 0.144 7.92 0.181 ;
     RECT  7.944 0.144 8.064 0.181 ;
     RECT  8.088 0.144 8.208 0.181 ;
     RECT  8.232 0.144 8.352 0.181 ;
     RECT  8.376 0.144 8.544 0.181 ;
     RECT  8.568 0.144 8.688 0.181 ;
     RECT  8.712 0.144 8.832 0.181 ;
     RECT  8.856 0.144 8.976 0.181 ;
     RECT  9 0.144 9.168 0.181 ;
     RECT  9.192 0.144 9.312 0.181 ;
     RECT  9.336 0.144 9.456 0.181 ;
     RECT  9.48 0.144 9.6 0.181 ;
     RECT  9.624 0.144 9.792 0.181 ;
     RECT  9.816 0.144 9.936 0.181 ;
     RECT  9.96 0.144 10.08 0.181 ;
     RECT  10.104 0.144 10.272 0.181 ;
     RECT  10.296 0.144 10.416 0.181 ;
     RECT  10.44 0.144 10.56 0.181 ;
     RECT  10.584 0.144 10.704 0.181 ;
     RECT  10.728 0.144 10.896 0.181 ;
     RECT  10.92 0.144 11.04 0.181 ;
     RECT  11.064 0.144 11.184 0.181 ;
     RECT  11.208 0.144 11.328 0.181 ;
     RECT  11.352 0.144 11.52 0.181 ;
     RECT  11.544 0.144 11.664 0.181 ;
     RECT  11.688 0.144 11.808 0.181 ;
     RECT  11.832 0.144 11.952 0.181 ;
     RECT  11.976 0.144 12.144 0.181 ;
     RECT  12.168 0.144 12.288 0.181 ;
     RECT  12.312 0.144 12.432 0.181 ;
     RECT  12.456 0.144 12.576 0.181 ;
     RECT  12.6 0.144 12.768 0.181 ;
     RECT  12.792 0.144 12.912 0.181 ;
     RECT  12.936 0.144 13.056 0.181 ;
     RECT  13.08 0.144 13.2 0.181 ;
     RECT  13.224 0.144 13.392 0.181 ;
     RECT  13.416 0.144 13.536 0.181 ;
     RECT  13.56 0.144 13.68 0.181 ;
     RECT  13.704 0.144 13.824 0.181 ;
     RECT  13.848 0.144 14.016 0.181 ;
     RECT  14.04 0.144 14.16 0.181 ;
     RECT  14.184 0.144 14.304 0.181 ;
     RECT  14.328 0.144 14.496 0.181 ;
     RECT  14.52 0.144 14.64 0.181 ;
     RECT  14.664 0.144 14.784 0.181 ;
     RECT  14.808 0.144 14.928 0.181 ;
     RECT  14.952 0.144 15.12 0.181 ;
     RECT  15.144 0.144 15.264 0.181 ;
     RECT  15.288 0.144 15.408 0.181 ;
     RECT  15.432 0.144 15.552 0.181 ;
     RECT  15.576 0.144 15.744 0.181 ;
     RECT  15.768 0.144 15.888 0.181 ;
     RECT  15.912 0.144 16.032 0.181 ;
     RECT  16.056 0.144 16.176 0.181 ;
     RECT  16.2 0.144 16.368 0.181 ;
     RECT  16.392 0.144 16.512 0.181 ;
     RECT  16.536 0.144 16.656 0.181 ;
     RECT  16.68 0.144 16.8 0.181 ;
     RECT  16.824 0.144 16.992 0.181 ;
     RECT  17.016 0.144 17.136 0.181 ;
     RECT  17.16 0.144 17.28 0.181 ;
     RECT  17.304 0.144 17.472 0.181 ;
     RECT  17.496 0.144 17.616 0.181 ;
     RECT  17.64 0.144 17.76 0.181 ;
     RECT  17.784 0.144 17.904 0.181 ;
     RECT  17.928 0.144 18.096 0.181 ;
     RECT  18.12 0.144 18.24 0.181 ;
     RECT  18.264 0.144 18.384 0.181 ;
     RECT  18.408 0.144 18.528 0.181 ;
     RECT  18.552 0.144 18.72 0.181 ;
     RECT  18.744 0.144 18.864 0.181 ;
     RECT  18.888 0.144 19.008 0.181 ;
     RECT  19.032 0.144 19.152 0.181 ;
     RECT  19.176 0.144 19.344 0.181 ;
     RECT  19.368 0.144 19.488 0.181 ;
     RECT  19.512 0.144 19.632 0.181 ;
     RECT  19.656 0.144 19.776 0.181 ;
     RECT  19.8 0.144 19.968 0.181 ;
     RECT  19.992 0.144 20.112 0.181 ;
     RECT  20.136 0.144 20.256 0.181 ;
     RECT  20.28 0.144 20.4 0.181 ;
     RECT  20.424 0.144 20.592 0.181 ;
     RECT  20.616 0.144 20.736 0.181 ;
     RECT  20.76 0.144 20.88 0.181 ;
     RECT  20.904 0.144 21.072 0.181 ;
     RECT  21.096 0.144 21.216 0.181 ;
     RECT  21.24 0.144 21.36 0.181 ;
     RECT  21.384 0.144 21.504 0.181 ;
     RECT  21.528 0.144 21.696 0.181 ;
     RECT  21.72 0.144 21.84 0.181 ;
     RECT  21.864 0.144 21.984 0.181 ;
     RECT  22.008 0.144 22.128 0.181 ;
     RECT  22.152 0.144 22.32 0.181 ;
     RECT  22.344 0.144 22.464 0.181 ;
     RECT  22.488 0.144 22.608 0.181 ;
     RECT  22.632 0.144 22.752 0.181 ;
     RECT  22.776 0.144 22.944 0.181 ;
     RECT  22.968 0.144 23.088 0.181 ;
     RECT  23.112 0.144 23.232 0.181 ;
     RECT  23.256 0.144 23.376 0.181 ;
     RECT  23.4 0.144 23.568 0.181 ;
     RECT  23.592 0.144 23.712 0.181 ;
     RECT  1.392 0.181 2.256 0.192 ;
     RECT  2.28 0.181 2.4 0.192 ;
     RECT  2.424 0.181 2.592 0.192 ;
     RECT  2.616 0.181 2.736 0.192 ;
     RECT  2.76 0.181 2.88 0.192 ;
     RECT  2.904 0.181 3.072 0.192 ;
     RECT  3.096 0.181 3.216 0.192 ;
     RECT  3.24 0.181 3.36 0.192 ;
     RECT  3.384 0.181 3.504 0.192 ;
     RECT  3.528 0.181 3.696 0.192 ;
     RECT  3.72 0.181 3.84 0.192 ;
     RECT  3.864 0.181 3.984 0.192 ;
     RECT  4.008 0.181 4.128 0.192 ;
     RECT  4.152 0.181 4.32 0.192 ;
     RECT  4.344 0.181 4.464 0.192 ;
     RECT  4.488 0.181 4.608 0.192 ;
     RECT  4.632 0.181 4.752 0.192 ;
     RECT  4.776 0.181 4.944 0.192 ;
     RECT  4.968 0.181 5.088 0.192 ;
     RECT  5.112 0.181 5.232 0.192 ;
     RECT  5.256 0.181 5.376 0.192 ;
     RECT  5.4 0.181 5.568 0.192 ;
     RECT  5.592 0.181 5.712 0.192 ;
     RECT  5.736 0.181 5.856 0.192 ;
     RECT  5.88 0.181 6 0.192 ;
     RECT  6.024 0.181 6.192 0.192 ;
     RECT  6.216 0.181 6.336 0.192 ;
     RECT  6.36 0.181 6.48 0.192 ;
     RECT  6.504 0.181 6.624 0.192 ;
     RECT  6.648 0.181 6.816 0.192 ;
     RECT  6.84 0.181 6.96 0.192 ;
     RECT  6.984 0.181 7.104 0.192 ;
     RECT  7.128 0.181 7.296 0.192 ;
     RECT  7.32 0.181 7.44 0.192 ;
     RECT  7.464 0.181 7.584 0.192 ;
     RECT  7.608 0.181 7.728 0.192 ;
     RECT  7.752 0.181 7.92 0.192 ;
     RECT  7.944 0.181 8.064 0.192 ;
     RECT  8.088 0.181 8.208 0.192 ;
     RECT  8.232 0.181 8.352 0.192 ;
     RECT  8.376 0.181 8.544 0.192 ;
     RECT  8.568 0.181 8.688 0.192 ;
     RECT  8.712 0.181 8.832 0.192 ;
     RECT  8.856 0.181 8.976 0.192 ;
     RECT  9 0.181 9.168 0.192 ;
     RECT  9.192 0.181 9.312 0.192 ;
     RECT  9.336 0.181 9.456 0.192 ;
     RECT  9.48 0.181 9.6 0.192 ;
     RECT  9.624 0.181 9.792 0.192 ;
     RECT  9.816 0.181 9.936 0.192 ;
     RECT  9.96 0.181 10.08 0.192 ;
     RECT  10.104 0.181 10.272 0.192 ;
     RECT  10.296 0.181 10.416 0.192 ;
     RECT  10.44 0.181 10.56 0.192 ;
     RECT  10.584 0.181 10.704 0.192 ;
     RECT  10.728 0.181 10.896 0.192 ;
     RECT  10.92 0.181 11.04 0.192 ;
     RECT  11.064 0.181 11.184 0.192 ;
     RECT  11.208 0.181 11.328 0.192 ;
     RECT  11.352 0.181 11.52 0.192 ;
     RECT  11.544 0.181 11.664 0.192 ;
     RECT  11.688 0.181 11.808 0.192 ;
     RECT  11.832 0.181 11.952 0.192 ;
     RECT  11.976 0.181 12.144 0.192 ;
     RECT  12.168 0.181 12.288 0.192 ;
     RECT  12.312 0.181 12.432 0.192 ;
     RECT  12.456 0.181 12.576 0.192 ;
     RECT  12.6 0.181 12.768 0.192 ;
     RECT  12.792 0.181 12.912 0.192 ;
     RECT  12.936 0.181 13.056 0.192 ;
     RECT  13.08 0.181 13.2 0.192 ;
     RECT  13.224 0.181 13.392 0.192 ;
     RECT  13.416 0.181 13.536 0.192 ;
     RECT  13.56 0.181 13.68 0.192 ;
     RECT  13.704 0.181 13.824 0.192 ;
     RECT  13.848 0.181 14.016 0.192 ;
     RECT  14.04 0.181 14.16 0.192 ;
     RECT  14.184 0.181 14.304 0.192 ;
     RECT  14.328 0.181 14.496 0.192 ;
     RECT  14.52 0.181 14.64 0.192 ;
     RECT  14.664 0.181 14.784 0.192 ;
     RECT  14.808 0.181 14.928 0.192 ;
     RECT  14.952 0.181 15.12 0.192 ;
     RECT  15.144 0.181 15.264 0.192 ;
     RECT  15.288 0.181 15.408 0.192 ;
     RECT  15.432 0.181 15.552 0.192 ;
     RECT  15.576 0.181 15.744 0.192 ;
     RECT  15.768 0.181 15.888 0.192 ;
     RECT  15.912 0.181 16.032 0.192 ;
     RECT  16.056 0.181 16.176 0.192 ;
     RECT  16.2 0.181 16.368 0.192 ;
     RECT  16.392 0.181 16.512 0.192 ;
     RECT  16.536 0.181 16.656 0.192 ;
     RECT  16.68 0.181 16.8 0.192 ;
     RECT  16.824 0.181 16.992 0.192 ;
     RECT  17.016 0.181 17.136 0.192 ;
     RECT  17.16 0.181 17.28 0.192 ;
     RECT  17.304 0.181 17.472 0.192 ;
     RECT  17.496 0.181 17.616 0.192 ;
     RECT  17.64 0.181 17.76 0.192 ;
     RECT  17.784 0.181 17.904 0.192 ;
     RECT  17.928 0.181 18.096 0.192 ;
     RECT  18.12 0.181 18.24 0.192 ;
     RECT  18.264 0.181 18.384 0.192 ;
     RECT  18.408 0.181 18.528 0.192 ;
     RECT  18.552 0.181 18.72 0.192 ;
     RECT  18.744 0.181 18.864 0.192 ;
     RECT  18.888 0.181 19.008 0.192 ;
     RECT  19.032 0.181 19.152 0.192 ;
     RECT  19.176 0.181 19.344 0.192 ;
     RECT  19.368 0.181 19.488 0.192 ;
     RECT  19.512 0.181 19.632 0.192 ;
     RECT  19.656 0.181 19.776 0.192 ;
     RECT  19.8 0.181 19.968 0.192 ;
     RECT  19.992 0.181 20.112 0.192 ;
     RECT  20.136 0.181 20.256 0.192 ;
     RECT  20.28 0.181 20.4 0.192 ;
     RECT  20.424 0.181 20.592 0.192 ;
     RECT  20.616 0.181 20.736 0.192 ;
     RECT  20.76 0.181 20.88 0.192 ;
     RECT  20.904 0.181 21.072 0.192 ;
     RECT  21.096 0.181 21.216 0.192 ;
     RECT  21.24 0.181 21.36 0.192 ;
     RECT  21.384 0.181 21.504 0.192 ;
     RECT  21.528 0.181 21.696 0.192 ;
     RECT  21.72 0.181 21.84 0.192 ;
     RECT  21.864 0.181 21.984 0.192 ;
     RECT  22.008 0.181 22.128 0.192 ;
     RECT  22.152 0.181 22.32 0.192 ;
     RECT  22.344 0.181 22.464 0.192 ;
     RECT  22.488 0.181 22.608 0.192 ;
     RECT  22.632 0.181 22.752 0.192 ;
     RECT  22.776 0.181 22.944 0.192 ;
     RECT  22.968 0.181 23.088 0.192 ;
     RECT  23.112 0.181 23.232 0.192 ;
     RECT  23.256 0.181 23.376 0.192 ;
     RECT  23.4 0.181 23.568 0.192 ;
     RECT  23.592 0.181 23.712 0.192 ;
     RECT  23.736 0.181 23.832 0.192 ;
     RECT  1.392 0.192 23.832 1.909 ;
     RECT  0.432 1.909 23.832 2.005 ;
     RECT  0.432 2.005 24.312 2.485 ;
     RECT  0.432 2.485 24.936 2.773 ;
     RECT  0.288 2.773 24.936 5.125 ;
     RECT  0.288 5.125 24.984 5.413 ;
     RECT  0.288 5.413 25.656 5.653 ;
     RECT  0.288 5.653 25.752 8.771 ;
     RECT  0.288 8.771 24.936 10.883 ;
     RECT  0.288 10.883 19.272 10.931 ;
     RECT  7.536 10.931 19.272 11.123 ;
     RECT  18 11.123 19.272 11.363 ;
     RECT  7.536 11.123 16.776 11.411 ;
     RECT  15.36 11.411 16.776 11.459 ;
     RECT  18.192 11.363 19.272 11.459 ;
     RECT  20.256 10.883 24.936 11.507 ;
     RECT  18.6 11.459 19.272 11.555 ;
     RECT  7.536 11.411 13.944 12.035 ;
     RECT  9.648 12.035 13.944 12.517 ;
     RECT  15.696 11.459 16.776 12.517 ;
     RECT  9.648 12.517 16.776 12.563 ;
     RECT  20.496 11.507 24.936 12.851 ;
     RECT  9.888 12.563 11.256 13.139 ;
     RECT  12.24 12.563 16.776 13.621 ;
     RECT  18.6 11.555 18.912 13.669 ;
     RECT  18.336 13.669 18.912 14.197 ;
     RECT  12.24 13.621 17.016 14.245 ;
     RECT  18.336 14.197 19.128 14.245 ;
     RECT  0.288 10.931 6.504 14.483 ;
     RECT  20.496 12.851 24.888 14.675 ;
     RECT  20.496 14.675 24.696 14.771 ;
     RECT  1.68 14.483 6.504 14.821 ;
     RECT  7.536 12.035 8.112 14.821 ;
     RECT  9.888 13.139 10.812 14.821 ;
     RECT  12.096 14.245 17.016 14.821 ;
     RECT  18 14.245 19.128 14.821 ;
     RECT  20.496 14.771 24.168 14.821 ;
     RECT  0.288 14.483 0.312 14.963 ;
     RECT  1.68 14.821 24.168 15.011 ;
     RECT  2.256 15.011 24.168 15.059 ;
     RECT  2.256 15.059 23.64 17.088 ;
     RECT  2.28 17.088 2.4 17.104 ;
     RECT  2.424 17.088 2.592 17.104 ;
     RECT  2.616 17.088 2.736 17.104 ;
     RECT  2.76 17.088 2.88 17.104 ;
     RECT  2.904 17.088 3.024 17.104 ;
     RECT  3.048 17.088 3.216 17.104 ;
     RECT  3.24 17.088 3.36 17.104 ;
     RECT  3.384 17.088 3.504 17.104 ;
     RECT  3.528 17.088 3.648 17.104 ;
     RECT  3.672 17.088 3.84 17.104 ;
     RECT  3.864 17.088 3.984 17.104 ;
     RECT  4.008 17.088 4.128 17.104 ;
     RECT  4.152 17.088 4.272 17.104 ;
     RECT  4.296 17.088 4.464 17.104 ;
     RECT  4.488 17.088 4.608 17.104 ;
     RECT  4.632 17.088 4.752 17.104 ;
     RECT  4.776 17.088 4.896 17.104 ;
     RECT  4.92 17.088 5.088 17.104 ;
     RECT  5.112 17.088 5.232 17.104 ;
     RECT  5.256 17.088 5.376 17.104 ;
     RECT  5.4 17.088 5.52 17.104 ;
     RECT  5.544 17.088 5.712 17.104 ;
     RECT  5.736 17.088 5.856 17.104 ;
     RECT  5.88 17.088 6 17.104 ;
     RECT  6.024 17.088 6.144 17.104 ;
     RECT  6.168 17.088 6.336 17.104 ;
     RECT  6.36 17.088 6.48 17.104 ;
     RECT  6.504 17.088 6.624 17.104 ;
     RECT  6.648 17.088 6.768 17.104 ;
     RECT  6.792 17.088 6.96 17.104 ;
     RECT  6.984 17.088 7.104 17.104 ;
     RECT  7.128 17.088 7.248 17.104 ;
     RECT  7.272 17.088 7.392 17.104 ;
     RECT  7.416 17.088 7.584 17.104 ;
     RECT  7.608 17.088 7.728 17.104 ;
     RECT  7.752 17.088 7.872 17.104 ;
     RECT  7.896 17.088 8.016 17.104 ;
     RECT  8.04 17.088 8.208 17.104 ;
     RECT  8.232 17.088 8.352 17.104 ;
     RECT  8.376 17.088 8.496 17.104 ;
     RECT  8.52 17.088 8.64 17.104 ;
     RECT  8.664 17.088 8.832 17.104 ;
     RECT  8.856 17.088 8.976 17.104 ;
     RECT  9 17.088 9.12 17.104 ;
     RECT  9.144 17.088 9.264 17.104 ;
     RECT  9.288 17.088 9.456 17.104 ;
     RECT  9.48 17.088 9.6 17.104 ;
     RECT  9.624 17.088 9.744 17.104 ;
     RECT  9.768 17.088 9.888 17.104 ;
     RECT  9.912 17.088 10.08 17.104 ;
     RECT  10.104 17.088 10.224 17.104 ;
     RECT  10.248 17.088 10.368 17.104 ;
     RECT  10.392 17.088 10.512 17.104 ;
     RECT  10.536 17.088 10.704 17.104 ;
     RECT  10.728 17.088 10.848 17.104 ;
     RECT  10.872 17.088 10.992 17.104 ;
     RECT  11.016 17.088 11.136 17.104 ;
     RECT  11.16 17.088 11.328 17.104 ;
     RECT  11.352 17.088 11.472 17.104 ;
     RECT  11.496 17.088 11.616 17.104 ;
     RECT  11.64 17.088 11.76 17.104 ;
     RECT  11.784 17.088 11.952 17.104 ;
     RECT  11.976 17.088 12.096 17.104 ;
     RECT  12.12 17.088 12.24 17.104 ;
     RECT  12.264 17.088 12.384 17.104 ;
     RECT  12.408 17.088 12.576 17.104 ;
     RECT  12.6 17.088 12.72 17.104 ;
     RECT  12.744 17.088 12.864 17.104 ;
     RECT  12.888 17.088 13.008 17.104 ;
     RECT  13.032 17.088 13.2 17.104 ;
     RECT  13.224 17.088 13.344 17.104 ;
     RECT  13.368 17.088 13.488 17.104 ;
     RECT  13.512 17.088 13.632 17.104 ;
     RECT  13.656 17.088 13.824 17.104 ;
     RECT  13.848 17.088 13.968 17.104 ;
     RECT  13.992 17.088 14.112 17.104 ;
     RECT  14.136 17.088 14.256 17.104 ;
     RECT  14.28 17.088 14.448 17.104 ;
     RECT  14.472 17.088 14.592 17.104 ;
     RECT  14.616 17.088 14.736 17.104 ;
     RECT  14.76 17.088 14.88 17.104 ;
     RECT  14.904 17.088 15.072 17.104 ;
     RECT  15.096 17.088 15.216 17.104 ;
     RECT  15.24 17.088 15.36 17.104 ;
     RECT  15.384 17.088 15.504 17.104 ;
     RECT  15.528 17.088 15.696 17.104 ;
     RECT  15.72 17.088 15.84 17.104 ;
     RECT  15.864 17.088 15.984 17.104 ;
     RECT  16.008 17.088 16.128 17.104 ;
     RECT  16.152 17.088 16.32 17.104 ;
     RECT  16.344 17.088 16.464 17.104 ;
     RECT  16.488 17.088 16.608 17.104 ;
     RECT  16.632 17.088 16.752 17.104 ;
     RECT  16.776 17.088 16.944 17.104 ;
     RECT  16.968 17.088 17.088 17.104 ;
     RECT  17.112 17.088 17.232 17.104 ;
     RECT  17.256 17.088 17.376 17.104 ;
     RECT  17.4 17.088 17.568 17.104 ;
     RECT  17.592 17.088 17.712 17.104 ;
     RECT  17.736 17.088 17.856 17.104 ;
     RECT  17.88 17.088 18 17.104 ;
     RECT  18.024 17.088 18.192 17.104 ;
     RECT  18.216 17.088 18.336 17.104 ;
     RECT  18.36 17.088 18.48 17.104 ;
     RECT  18.504 17.088 18.624 17.104 ;
     RECT  18.648 17.088 18.816 17.104 ;
     RECT  18.84 17.088 18.96 17.104 ;
     RECT  18.984 17.088 19.104 17.104 ;
     RECT  19.128 17.088 19.248 17.104 ;
     RECT  19.272 17.088 19.44 17.104 ;
     RECT  19.464 17.088 19.584 17.104 ;
     RECT  19.608 17.088 19.728 17.104 ;
     RECT  19.752 17.088 19.872 17.104 ;
     RECT  19.896 17.088 20.064 17.104 ;
     RECT  20.088 17.088 20.208 17.104 ;
     RECT  20.232 17.088 20.352 17.104 ;
     RECT  20.376 17.088 20.496 17.104 ;
     RECT  20.52 17.088 20.688 17.104 ;
     RECT  20.712 17.088 20.832 17.104 ;
     RECT  20.856 17.088 20.976 17.104 ;
     RECT  21 17.088 21.12 17.104 ;
     RECT  21.144 17.088 21.312 17.104 ;
     RECT  21.336 17.088 21.456 17.104 ;
     RECT  21.48 17.088 21.6 17.104 ;
     RECT  21.624 17.088 21.744 17.104 ;
     RECT  21.768 17.088 21.936 17.104 ;
     RECT  21.96 17.088 22.08 17.104 ;
     RECT  22.104 17.088 22.224 17.104 ;
     RECT  22.248 17.088 22.368 17.104 ;
     RECT  22.392 17.088 22.56 17.104 ;
     RECT  22.584 17.088 22.704 17.104 ;
     RECT  22.728 17.088 22.848 17.104 ;
     RECT  22.872 17.088 22.992 17.104 ;
     RECT  23.016 17.088 23.184 17.104 ;
     RECT  23.208 17.088 23.328 17.104 ;
     RECT  23.352 17.088 23.472 17.104 ;
     RECT  23.496 17.088 23.616 17.104 ;
     RECT  19.272 10.883 20.256 11.507 ;
     RECT  6.504 10.931 7.536 14.821 ;
     RECT  16.776 11.123 18 11.363 ;
     RECT  16.776 11.363 18.192 11.459 ;
     RECT  13.944 11.411 15.36 11.459 ;
     RECT  13.944 11.459 15.696 12.517 ;
     RECT  19.272 11.507 20.496 11.555 ;
     RECT  11.256 12.563 12.24 13.139 ;
     RECT  10.812 13.139 12.24 14.245 ;
     RECT  17.016 13.669 18.336 14.245 ;
     RECT  19.128 14.197 20.496 14.821 ;
     RECT  10.812 14.245 12.096 14.821 ;
     RECT  17.016 14.245 18 14.821 ;
     RECT  0.312 14.483 1.68 14.963 ;
  END
END dsfd_dvrly_276_SN
END LIBRARY
